# Generated by FakeRAM 2.0 (routing-friendly)
VERSION 5.7 ;
BUSBITCHARS "[]" ;
PROPERTYDEFINITIONS
  MACRO width INTEGER ;
  MACRO depth INTEGER ;
  MACRO banks INTEGER ;
END PROPERTYDEFINITIONS
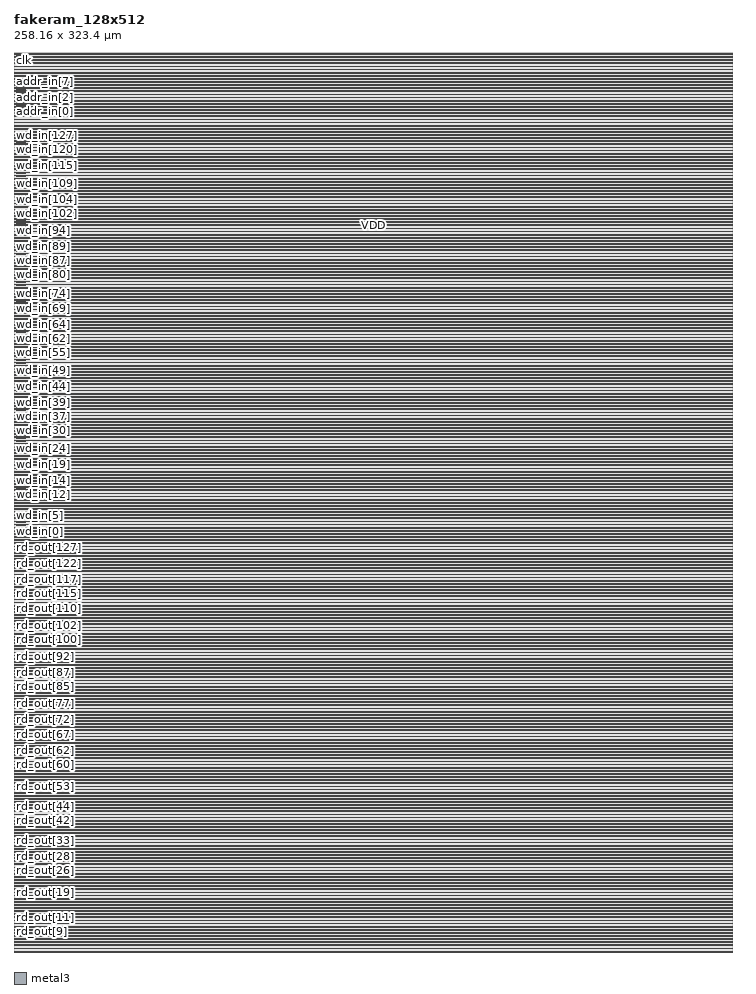
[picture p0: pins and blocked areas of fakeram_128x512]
MACRO fakeram_128x512
  PROPERTY width 128 ;
  PROPERTY depth 512 ;
  PROPERTY banks 4 ;
  FOREIGN fakeram_128x512 0 0 ;
  SYMMETRY X Y R90 ;
  SIZE 258.160 BY 323.400 ;
  CLASS BLOCK ;
  PIN rd_out[0]
    DIRECTION OUTPUT ;
    USE SIGNAL ;
    PORT
      LAYER metal3 ;
      RECT 1.000 0.140 3.000 0.210 ;
    END
    PORT
      LAYER metal3 ;
      RECT 1.000 0.105 4.000 0.245 ;
    END
  END rd_out[0]
  PIN rd_out[1]
    DIRECTION OUTPUT ;
    USE SIGNAL ;
    PORT
      LAYER metal3 ;
      RECT 1.000 1.260 3.000 1.330 ;
    END
    PORT
      LAYER metal3 ;
      RECT 1.000 1.225 4.000 1.365 ;
    END
  END rd_out[1]
  PIN rd_out[2]
    DIRECTION OUTPUT ;
    USE SIGNAL ;
    PORT
      LAYER metal3 ;
      RECT 1.000 2.380 3.000 2.450 ;
    END
    PORT
      LAYER metal3 ;
      RECT 1.000 2.345 4.000 2.485 ;
    END
  END rd_out[2]
  PIN rd_out[3]
    DIRECTION OUTPUT ;
    USE SIGNAL ;
    PORT
      LAYER metal3 ;
      RECT 1.000 3.500 3.000 3.570 ;
    END
    PORT
      LAYER metal3 ;
      RECT 1.000 3.465 4.000 3.605 ;
    END
  END rd_out[3]
  PIN rd_out[4]
    DIRECTION OUTPUT ;
    USE SIGNAL ;
    PORT
      LAYER metal3 ;
      RECT 1.000 4.620 3.000 4.690 ;
    END
    PORT
      LAYER metal3 ;
      RECT 1.000 4.585 4.000 4.725 ;
    END
  END rd_out[4]
  PIN rd_out[5]
    DIRECTION OUTPUT ;
    USE SIGNAL ;
    PORT
      LAYER metal3 ;
      RECT 1.000 5.740 3.000 5.810 ;
    END
    PORT
      LAYER metal3 ;
      RECT 1.000 5.705 4.000 5.845 ;
    END
  END rd_out[5]
  PIN rd_out[6]
    DIRECTION OUTPUT ;
    USE SIGNAL ;
    PORT
      LAYER metal3 ;
      RECT 1.000 6.860 3.000 6.930 ;
    END
    PORT
      LAYER metal3 ;
      RECT 1.000 6.825 4.000 6.965 ;
    END
  END rd_out[6]
  PIN rd_out[7]
    DIRECTION OUTPUT ;
    USE SIGNAL ;
    PORT
      LAYER metal3 ;
      RECT 1.000 7.980 3.000 8.050 ;
    END
    PORT
      LAYER metal3 ;
      RECT 1.000 7.945 4.000 8.085 ;
    END
  END rd_out[7]
  PIN rd_out[8]
    DIRECTION OUTPUT ;
    USE SIGNAL ;
    PORT
      LAYER metal3 ;
      RECT 1.000 9.100 3.000 9.170 ;
    END
    PORT
      LAYER metal3 ;
      RECT 1.000 9.065 4.000 9.205 ;
    END
  END rd_out[8]
  PIN rd_out[9]
    DIRECTION OUTPUT ;
    USE SIGNAL ;
    PORT
      LAYER metal3 ;
      RECT 1.000 10.220 3.000 10.290 ;
    END
    PORT
      LAYER metal3 ;
      RECT 1.000 10.185 4.000 10.325 ;
    END
  END rd_out[9]
  PIN rd_out[10]
    DIRECTION OUTPUT ;
    USE SIGNAL ;
    PORT
      LAYER metal3 ;
      RECT 1.000 11.340 3.000 11.410 ;
    END
    PORT
      LAYER metal3 ;
      RECT 1.000 11.305 4.000 11.445 ;
    END
  END rd_out[10]
  PIN rd_out[11]
    DIRECTION OUTPUT ;
    USE SIGNAL ;
    PORT
      LAYER metal3 ;
      RECT 1.000 12.460 3.000 12.530 ;
    END
    PORT
      LAYER metal3 ;
      RECT 1.000 12.425 4.000 12.565 ;
    END
  END rd_out[11]
  PIN rd_out[12]
    DIRECTION OUTPUT ;
    USE SIGNAL ;
    PORT
      LAYER metal3 ;
      RECT 1.000 13.580 3.000 13.650 ;
    END
    PORT
      LAYER metal3 ;
      RECT 1.000 13.545 4.000 13.685 ;
    END
  END rd_out[12]
  PIN rd_out[13]
    DIRECTION OUTPUT ;
    USE SIGNAL ;
    PORT
      LAYER metal3 ;
      RECT 1.000 14.700 3.000 14.770 ;
    END
    PORT
      LAYER metal3 ;
      RECT 1.000 14.665 4.000 14.805 ;
    END
  END rd_out[13]
  PIN rd_out[14]
    DIRECTION OUTPUT ;
    USE SIGNAL ;
    PORT
      LAYER metal3 ;
      RECT 1.000 15.820 3.000 15.890 ;
    END
    PORT
      LAYER metal3 ;
      RECT 1.000 15.785 4.000 15.925 ;
    END
  END rd_out[14]
  PIN rd_out[15]
    DIRECTION OUTPUT ;
    USE SIGNAL ;
    PORT
      LAYER metal3 ;
      RECT 1.000 16.940 3.000 17.010 ;
    END
    PORT
      LAYER metal3 ;
      RECT 1.000 16.905 4.000 17.045 ;
    END
  END rd_out[15]
  PIN rd_out[16]
    DIRECTION OUTPUT ;
    USE SIGNAL ;
    PORT
      LAYER metal3 ;
      RECT 1.000 18.060 3.000 18.130 ;
    END
    PORT
      LAYER metal3 ;
      RECT 1.000 18.025 4.000 18.165 ;
    END
  END rd_out[16]
  PIN rd_out[17]
    DIRECTION OUTPUT ;
    USE SIGNAL ;
    PORT
      LAYER metal3 ;
      RECT 1.000 19.180 3.000 19.250 ;
    END
    PORT
      LAYER metal3 ;
      RECT 1.000 19.145 4.000 19.285 ;
    END
  END rd_out[17]
  PIN rd_out[18]
    DIRECTION OUTPUT ;
    USE SIGNAL ;
    PORT
      LAYER metal3 ;
      RECT 1.000 20.300 3.000 20.370 ;
    END
    PORT
      LAYER metal3 ;
      RECT 1.000 20.265 4.000 20.405 ;
    END
  END rd_out[18]
  PIN rd_out[19]
    DIRECTION OUTPUT ;
    USE SIGNAL ;
    PORT
      LAYER metal3 ;
      RECT 1.000 21.420 3.000 21.490 ;
    END
    PORT
      LAYER metal3 ;
      RECT 1.000 21.385 4.000 21.525 ;
    END
  END rd_out[19]
  PIN rd_out[20]
    DIRECTION OUTPUT ;
    USE SIGNAL ;
    PORT
      LAYER metal3 ;
      RECT 1.000 22.540 3.000 22.610 ;
    END
    PORT
      LAYER metal3 ;
      RECT 1.000 22.505 4.000 22.645 ;
    END
  END rd_out[20]
  PIN rd_out[21]
    DIRECTION OUTPUT ;
    USE SIGNAL ;
    PORT
      LAYER metal3 ;
      RECT 1.000 23.660 3.000 23.730 ;
    END
    PORT
      LAYER metal3 ;
      RECT 1.000 23.625 4.000 23.765 ;
    END
  END rd_out[21]
  PIN rd_out[22]
    DIRECTION OUTPUT ;
    USE SIGNAL ;
    PORT
      LAYER metal3 ;
      RECT 1.000 24.780 3.000 24.850 ;
    END
    PORT
      LAYER metal3 ;
      RECT 1.000 24.745 4.000 24.885 ;
    END
  END rd_out[22]
  PIN rd_out[23]
    DIRECTION OUTPUT ;
    USE SIGNAL ;
    PORT
      LAYER metal3 ;
      RECT 1.000 25.900 3.000 25.970 ;
    END
    PORT
      LAYER metal3 ;
      RECT 1.000 25.865 4.000 26.005 ;
    END
  END rd_out[23]
  PIN rd_out[24]
    DIRECTION OUTPUT ;
    USE SIGNAL ;
    PORT
      LAYER metal3 ;
      RECT 1.000 27.020 3.000 27.090 ;
    END
    PORT
      LAYER metal3 ;
      RECT 1.000 26.985 4.000 27.125 ;
    END
  END rd_out[24]
  PIN rd_out[25]
    DIRECTION OUTPUT ;
    USE SIGNAL ;
    PORT
      LAYER metal3 ;
      RECT 1.000 28.140 3.000 28.210 ;
    END
    PORT
      LAYER metal3 ;
      RECT 1.000 28.105 4.000 28.245 ;
    END
  END rd_out[25]
  PIN rd_out[26]
    DIRECTION OUTPUT ;
    USE SIGNAL ;
    PORT
      LAYER metal3 ;
      RECT 1.000 29.260 3.000 29.330 ;
    END
    PORT
      LAYER metal3 ;
      RECT 1.000 29.225 4.000 29.365 ;
    END
  END rd_out[26]
  PIN rd_out[27]
    DIRECTION OUTPUT ;
    USE SIGNAL ;
    PORT
      LAYER metal3 ;
      RECT 1.000 30.380 3.000 30.450 ;
    END
    PORT
      LAYER metal3 ;
      RECT 1.000 30.345 4.000 30.485 ;
    END
  END rd_out[27]
  PIN rd_out[28]
    DIRECTION OUTPUT ;
    USE SIGNAL ;
    PORT
      LAYER metal3 ;
      RECT 1.000 31.500 3.000 31.570 ;
    END
    PORT
      LAYER metal3 ;
      RECT 1.000 31.465 4.000 31.605 ;
    END
  END rd_out[28]
  PIN rd_out[29]
    DIRECTION OUTPUT ;
    USE SIGNAL ;
    PORT
      LAYER metal3 ;
      RECT 1.000 32.620 3.000 32.690 ;
    END
    PORT
      LAYER metal3 ;
      RECT 1.000 32.585 4.000 32.725 ;
    END
  END rd_out[29]
  PIN rd_out[30]
    DIRECTION OUTPUT ;
    USE SIGNAL ;
    PORT
      LAYER metal3 ;
      RECT 1.000 33.740 3.000 33.810 ;
    END
    PORT
      LAYER metal3 ;
      RECT 1.000 33.705 4.000 33.845 ;
    END
  END rd_out[30]
  PIN rd_out[31]
    DIRECTION OUTPUT ;
    USE SIGNAL ;
    PORT
      LAYER metal3 ;
      RECT 1.000 34.860 3.000 34.930 ;
    END
    PORT
      LAYER metal3 ;
      RECT 1.000 34.825 4.000 34.965 ;
    END
  END rd_out[31]
  PIN rd_out[32]
    DIRECTION OUTPUT ;
    USE SIGNAL ;
    PORT
      LAYER metal3 ;
      RECT 1.000 35.980 3.000 36.050 ;
    END
    PORT
      LAYER metal3 ;
      RECT 1.000 35.945 4.000 36.085 ;
    END
  END rd_out[32]
  PIN rd_out[33]
    DIRECTION OUTPUT ;
    USE SIGNAL ;
    PORT
      LAYER metal3 ;
      RECT 1.000 37.100 3.000 37.170 ;
    END
    PORT
      LAYER metal3 ;
      RECT 1.000 37.065 4.000 37.205 ;
    END
  END rd_out[33]
  PIN rd_out[34]
    DIRECTION OUTPUT ;
    USE SIGNAL ;
    PORT
      LAYER metal3 ;
      RECT 1.000 38.220 3.000 38.290 ;
    END
    PORT
      LAYER metal3 ;
      RECT 1.000 38.185 4.000 38.325 ;
    END
  END rd_out[34]
  PIN rd_out[35]
    DIRECTION OUTPUT ;
    USE SIGNAL ;
    PORT
      LAYER metal3 ;
      RECT 1.000 39.340 3.000 39.410 ;
    END
    PORT
      LAYER metal3 ;
      RECT 1.000 39.305 4.000 39.445 ;
    END
  END rd_out[35]
  PIN rd_out[36]
    DIRECTION OUTPUT ;
    USE SIGNAL ;
    PORT
      LAYER metal3 ;
      RECT 1.000 40.460 3.000 40.530 ;
    END
    PORT
      LAYER metal3 ;
      RECT 1.000 40.425 4.000 40.565 ;
    END
  END rd_out[36]
  PIN rd_out[37]
    DIRECTION OUTPUT ;
    USE SIGNAL ;
    PORT
      LAYER metal3 ;
      RECT 1.000 41.580 3.000 41.650 ;
    END
    PORT
      LAYER metal3 ;
      RECT 1.000 41.545 4.000 41.685 ;
    END
  END rd_out[37]
  PIN rd_out[38]
    DIRECTION OUTPUT ;
    USE SIGNAL ;
    PORT
      LAYER metal3 ;
      RECT 1.000 42.700 3.000 42.770 ;
    END
    PORT
      LAYER metal3 ;
      RECT 1.000 42.665 4.000 42.805 ;
    END
  END rd_out[38]
  PIN rd_out[39]
    DIRECTION OUTPUT ;
    USE SIGNAL ;
    PORT
      LAYER metal3 ;
      RECT 1.000 43.820 3.000 43.890 ;
    END
    PORT
      LAYER metal3 ;
      RECT 1.000 43.785 4.000 43.925 ;
    END
  END rd_out[39]
  PIN rd_out[40]
    DIRECTION OUTPUT ;
    USE SIGNAL ;
    PORT
      LAYER metal3 ;
      RECT 1.000 44.940 3.000 45.010 ;
    END
    PORT
      LAYER metal3 ;
      RECT 1.000 44.905 4.000 45.045 ;
    END
  END rd_out[40]
  PIN rd_out[41]
    DIRECTION OUTPUT ;
    USE SIGNAL ;
    PORT
      LAYER metal3 ;
      RECT 1.000 46.060 3.000 46.130 ;
    END
    PORT
      LAYER metal3 ;
      RECT 1.000 46.025 4.000 46.165 ;
    END
  END rd_out[41]
  PIN rd_out[42]
    DIRECTION OUTPUT ;
    USE SIGNAL ;
    PORT
      LAYER metal3 ;
      RECT 1.000 47.180 3.000 47.250 ;
    END
    PORT
      LAYER metal3 ;
      RECT 1.000 47.145 4.000 47.285 ;
    END
  END rd_out[42]
  PIN rd_out[43]
    DIRECTION OUTPUT ;
    USE SIGNAL ;
    PORT
      LAYER metal3 ;
      RECT 1.000 48.300 3.000 48.370 ;
    END
    PORT
      LAYER metal3 ;
      RECT 1.000 48.265 4.000 48.405 ;
    END
  END rd_out[43]
  PIN rd_out[44]
    DIRECTION OUTPUT ;
    USE SIGNAL ;
    PORT
      LAYER metal3 ;
      RECT 1.000 49.420 3.000 49.490 ;
    END
    PORT
      LAYER metal3 ;
      RECT 1.000 49.385 4.000 49.525 ;
    END
  END rd_out[44]
  PIN rd_out[45]
    DIRECTION OUTPUT ;
    USE SIGNAL ;
    PORT
      LAYER metal3 ;
      RECT 1.000 50.540 3.000 50.610 ;
    END
    PORT
      LAYER metal3 ;
      RECT 1.000 50.505 4.000 50.645 ;
    END
  END rd_out[45]
  PIN rd_out[46]
    DIRECTION OUTPUT ;
    USE SIGNAL ;
    PORT
      LAYER metal3 ;
      RECT 1.000 51.660 3.000 51.730 ;
    END
    PORT
      LAYER metal3 ;
      RECT 1.000 51.625 4.000 51.765 ;
    END
  END rd_out[46]
  PIN rd_out[47]
    DIRECTION OUTPUT ;
    USE SIGNAL ;
    PORT
      LAYER metal3 ;
      RECT 1.000 52.780 3.000 52.850 ;
    END
    PORT
      LAYER metal3 ;
      RECT 1.000 52.745 4.000 52.885 ;
    END
  END rd_out[47]
  PIN rd_out[48]
    DIRECTION OUTPUT ;
    USE SIGNAL ;
    PORT
      LAYER metal3 ;
      RECT 1.000 53.900 3.000 53.970 ;
    END
    PORT
      LAYER metal3 ;
      RECT 1.000 53.865 4.000 54.005 ;
    END
  END rd_out[48]
  PIN rd_out[49]
    DIRECTION OUTPUT ;
    USE SIGNAL ;
    PORT
      LAYER metal3 ;
      RECT 1.000 55.020 3.000 55.090 ;
    END
    PORT
      LAYER metal3 ;
      RECT 1.000 54.985 4.000 55.125 ;
    END
  END rd_out[49]
  PIN rd_out[50]
    DIRECTION OUTPUT ;
    USE SIGNAL ;
    PORT
      LAYER metal3 ;
      RECT 1.000 56.140 3.000 56.210 ;
    END
    PORT
      LAYER metal3 ;
      RECT 1.000 56.105 4.000 56.245 ;
    END
  END rd_out[50]
  PIN rd_out[51]
    DIRECTION OUTPUT ;
    USE SIGNAL ;
    PORT
      LAYER metal3 ;
      RECT 1.000 57.260 3.000 57.330 ;
    END
    PORT
      LAYER metal3 ;
      RECT 1.000 57.225 4.000 57.365 ;
    END
  END rd_out[51]
  PIN rd_out[52]
    DIRECTION OUTPUT ;
    USE SIGNAL ;
    PORT
      LAYER metal3 ;
      RECT 1.000 58.380 3.000 58.450 ;
    END
    PORT
      LAYER metal3 ;
      RECT 1.000 58.345 4.000 58.485 ;
    END
  END rd_out[52]
  PIN rd_out[53]
    DIRECTION OUTPUT ;
    USE SIGNAL ;
    PORT
      LAYER metal3 ;
      RECT 1.000 59.500 3.000 59.570 ;
    END
    PORT
      LAYER metal3 ;
      RECT 1.000 59.465 4.000 59.605 ;
    END
  END rd_out[53]
  PIN rd_out[54]
    DIRECTION OUTPUT ;
    USE SIGNAL ;
    PORT
      LAYER metal3 ;
      RECT 1.000 60.620 3.000 60.690 ;
    END
    PORT
      LAYER metal3 ;
      RECT 1.000 60.585 4.000 60.725 ;
    END
  END rd_out[54]
  PIN rd_out[55]
    DIRECTION OUTPUT ;
    USE SIGNAL ;
    PORT
      LAYER metal3 ;
      RECT 1.000 61.740 3.000 61.810 ;
    END
    PORT
      LAYER metal3 ;
      RECT 1.000 61.705 4.000 61.845 ;
    END
  END rd_out[55]
  PIN rd_out[56]
    DIRECTION OUTPUT ;
    USE SIGNAL ;
    PORT
      LAYER metal3 ;
      RECT 1.000 62.860 3.000 62.930 ;
    END
    PORT
      LAYER metal3 ;
      RECT 1.000 62.825 4.000 62.965 ;
    END
  END rd_out[56]
  PIN rd_out[57]
    DIRECTION OUTPUT ;
    USE SIGNAL ;
    PORT
      LAYER metal3 ;
      RECT 1.000 63.980 3.000 64.050 ;
    END
    PORT
      LAYER metal3 ;
      RECT 1.000 63.945 4.000 64.085 ;
    END
  END rd_out[57]
  PIN rd_out[58]
    DIRECTION OUTPUT ;
    USE SIGNAL ;
    PORT
      LAYER metal3 ;
      RECT 1.000 65.100 3.000 65.170 ;
    END
    PORT
      LAYER metal3 ;
      RECT 1.000 65.065 4.000 65.205 ;
    END
  END rd_out[58]
  PIN rd_out[59]
    DIRECTION OUTPUT ;
    USE SIGNAL ;
    PORT
      LAYER metal3 ;
      RECT 1.000 66.220 3.000 66.290 ;
    END
    PORT
      LAYER metal3 ;
      RECT 1.000 66.185 4.000 66.325 ;
    END
  END rd_out[59]
  PIN rd_out[60]
    DIRECTION OUTPUT ;
    USE SIGNAL ;
    PORT
      LAYER metal3 ;
      RECT 1.000 67.340 3.000 67.410 ;
    END
    PORT
      LAYER metal3 ;
      RECT 1.000 67.305 4.000 67.445 ;
    END
  END rd_out[60]
  PIN rd_out[61]
    DIRECTION OUTPUT ;
    USE SIGNAL ;
    PORT
      LAYER metal3 ;
      RECT 1.000 68.460 3.000 68.530 ;
    END
    PORT
      LAYER metal3 ;
      RECT 1.000 68.425 4.000 68.565 ;
    END
  END rd_out[61]
  PIN rd_out[62]
    DIRECTION OUTPUT ;
    USE SIGNAL ;
    PORT
      LAYER metal3 ;
      RECT 1.000 69.580 3.000 69.650 ;
    END
    PORT
      LAYER metal3 ;
      RECT 1.000 69.545 4.000 69.685 ;
    END
  END rd_out[62]
  PIN rd_out[63]
    DIRECTION OUTPUT ;
    USE SIGNAL ;
    PORT
      LAYER metal3 ;
      RECT 1.000 70.700 3.000 70.770 ;
    END
    PORT
      LAYER metal3 ;
      RECT 1.000 70.665 4.000 70.805 ;
    END
  END rd_out[63]
  PIN rd_out[64]
    DIRECTION OUTPUT ;
    USE SIGNAL ;
    PORT
      LAYER metal3 ;
      RECT 1.000 71.820 3.000 71.890 ;
    END
    PORT
      LAYER metal3 ;
      RECT 1.000 71.785 4.000 71.925 ;
    END
  END rd_out[64]
  PIN rd_out[65]
    DIRECTION OUTPUT ;
    USE SIGNAL ;
    PORT
      LAYER metal3 ;
      RECT 1.000 72.940 3.000 73.010 ;
    END
    PORT
      LAYER metal3 ;
      RECT 1.000 72.905 4.000 73.045 ;
    END
  END rd_out[65]
  PIN rd_out[66]
    DIRECTION OUTPUT ;
    USE SIGNAL ;
    PORT
      LAYER metal3 ;
      RECT 1.000 74.060 3.000 74.130 ;
    END
    PORT
      LAYER metal3 ;
      RECT 1.000 74.025 4.000 74.165 ;
    END
  END rd_out[66]
  PIN rd_out[67]
    DIRECTION OUTPUT ;
    USE SIGNAL ;
    PORT
      LAYER metal3 ;
      RECT 1.000 75.180 3.000 75.250 ;
    END
    PORT
      LAYER metal3 ;
      RECT 1.000 75.145 4.000 75.285 ;
    END
  END rd_out[67]
  PIN rd_out[68]
    DIRECTION OUTPUT ;
    USE SIGNAL ;
    PORT
      LAYER metal3 ;
      RECT 1.000 76.300 3.000 76.370 ;
    END
    PORT
      LAYER metal3 ;
      RECT 1.000 76.265 4.000 76.405 ;
    END
  END rd_out[68]
  PIN rd_out[69]
    DIRECTION OUTPUT ;
    USE SIGNAL ;
    PORT
      LAYER metal3 ;
      RECT 1.000 77.420 3.000 77.490 ;
    END
    PORT
      LAYER metal3 ;
      RECT 1.000 77.385 4.000 77.525 ;
    END
  END rd_out[69]
  PIN rd_out[70]
    DIRECTION OUTPUT ;
    USE SIGNAL ;
    PORT
      LAYER metal3 ;
      RECT 1.000 78.540 3.000 78.610 ;
    END
    PORT
      LAYER metal3 ;
      RECT 1.000 78.505 4.000 78.645 ;
    END
  END rd_out[70]
  PIN rd_out[71]
    DIRECTION OUTPUT ;
    USE SIGNAL ;
    PORT
      LAYER metal3 ;
      RECT 1.000 79.660 3.000 79.730 ;
    END
    PORT
      LAYER metal3 ;
      RECT 1.000 79.625 4.000 79.765 ;
    END
  END rd_out[71]
  PIN rd_out[72]
    DIRECTION OUTPUT ;
    USE SIGNAL ;
    PORT
      LAYER metal3 ;
      RECT 1.000 80.780 3.000 80.850 ;
    END
    PORT
      LAYER metal3 ;
      RECT 1.000 80.745 4.000 80.885 ;
    END
  END rd_out[72]
  PIN rd_out[73]
    DIRECTION OUTPUT ;
    USE SIGNAL ;
    PORT
      LAYER metal3 ;
      RECT 1.000 81.900 3.000 81.970 ;
    END
    PORT
      LAYER metal3 ;
      RECT 1.000 81.865 4.000 82.005 ;
    END
  END rd_out[73]
  PIN rd_out[74]
    DIRECTION OUTPUT ;
    USE SIGNAL ;
    PORT
      LAYER metal3 ;
      RECT 1.000 83.020 3.000 83.090 ;
    END
    PORT
      LAYER metal3 ;
      RECT 1.000 82.985 4.000 83.125 ;
    END
  END rd_out[74]
  PIN rd_out[75]
    DIRECTION OUTPUT ;
    USE SIGNAL ;
    PORT
      LAYER metal3 ;
      RECT 1.000 84.140 3.000 84.210 ;
    END
    PORT
      LAYER metal3 ;
      RECT 1.000 84.105 4.000 84.245 ;
    END
  END rd_out[75]
  PIN rd_out[76]
    DIRECTION OUTPUT ;
    USE SIGNAL ;
    PORT
      LAYER metal3 ;
      RECT 1.000 85.260 3.000 85.330 ;
    END
    PORT
      LAYER metal3 ;
      RECT 1.000 85.225 4.000 85.365 ;
    END
  END rd_out[76]
  PIN rd_out[77]
    DIRECTION OUTPUT ;
    USE SIGNAL ;
    PORT
      LAYER metal3 ;
      RECT 1.000 86.380 3.000 86.450 ;
    END
    PORT
      LAYER metal3 ;
      RECT 1.000 86.345 4.000 86.485 ;
    END
  END rd_out[77]
  PIN rd_out[78]
    DIRECTION OUTPUT ;
    USE SIGNAL ;
    PORT
      LAYER metal3 ;
      RECT 1.000 87.500 3.000 87.570 ;
    END
    PORT
      LAYER metal3 ;
      RECT 1.000 87.465 4.000 87.605 ;
    END
  END rd_out[78]
  PIN rd_out[79]
    DIRECTION OUTPUT ;
    USE SIGNAL ;
    PORT
      LAYER metal3 ;
      RECT 1.000 88.620 3.000 88.690 ;
    END
    PORT
      LAYER metal3 ;
      RECT 1.000 88.585 4.000 88.725 ;
    END
  END rd_out[79]
  PIN rd_out[80]
    DIRECTION OUTPUT ;
    USE SIGNAL ;
    PORT
      LAYER metal3 ;
      RECT 1.000 89.740 3.000 89.810 ;
    END
    PORT
      LAYER metal3 ;
      RECT 1.000 89.705 4.000 89.845 ;
    END
  END rd_out[80]
  PIN rd_out[81]
    DIRECTION OUTPUT ;
    USE SIGNAL ;
    PORT
      LAYER metal3 ;
      RECT 1.000 90.860 3.000 90.930 ;
    END
    PORT
      LAYER metal3 ;
      RECT 1.000 90.825 4.000 90.965 ;
    END
  END rd_out[81]
  PIN rd_out[82]
    DIRECTION OUTPUT ;
    USE SIGNAL ;
    PORT
      LAYER metal3 ;
      RECT 1.000 91.980 3.000 92.050 ;
    END
    PORT
      LAYER metal3 ;
      RECT 1.000 91.945 4.000 92.085 ;
    END
  END rd_out[82]
  PIN rd_out[83]
    DIRECTION OUTPUT ;
    USE SIGNAL ;
    PORT
      LAYER metal3 ;
      RECT 1.000 93.100 3.000 93.170 ;
    END
    PORT
      LAYER metal3 ;
      RECT 1.000 93.065 4.000 93.205 ;
    END
  END rd_out[83]
  PIN rd_out[84]
    DIRECTION OUTPUT ;
    USE SIGNAL ;
    PORT
      LAYER metal3 ;
      RECT 1.000 94.220 3.000 94.290 ;
    END
    PORT
      LAYER metal3 ;
      RECT 1.000 94.185 4.000 94.325 ;
    END
  END rd_out[84]
  PIN rd_out[85]
    DIRECTION OUTPUT ;
    USE SIGNAL ;
    PORT
      LAYER metal3 ;
      RECT 1.000 95.340 3.000 95.410 ;
    END
    PORT
      LAYER metal3 ;
      RECT 1.000 95.305 4.000 95.445 ;
    END
  END rd_out[85]
  PIN rd_out[86]
    DIRECTION OUTPUT ;
    USE SIGNAL ;
    PORT
      LAYER metal3 ;
      RECT 1.000 96.460 3.000 96.530 ;
    END
    PORT
      LAYER metal3 ;
      RECT 1.000 96.425 4.000 96.565 ;
    END
  END rd_out[86]
  PIN rd_out[87]
    DIRECTION OUTPUT ;
    USE SIGNAL ;
    PORT
      LAYER metal3 ;
      RECT 1.000 97.580 3.000 97.650 ;
    END
    PORT
      LAYER metal3 ;
      RECT 1.000 97.545 4.000 97.685 ;
    END
  END rd_out[87]
  PIN rd_out[88]
    DIRECTION OUTPUT ;
    USE SIGNAL ;
    PORT
      LAYER metal3 ;
      RECT 1.000 98.700 3.000 98.770 ;
    END
    PORT
      LAYER metal3 ;
      RECT 1.000 98.665 4.000 98.805 ;
    END
  END rd_out[88]
  PIN rd_out[89]
    DIRECTION OUTPUT ;
    USE SIGNAL ;
    PORT
      LAYER metal3 ;
      RECT 1.000 99.820 3.000 99.890 ;
    END
    PORT
      LAYER metal3 ;
      RECT 1.000 99.785 4.000 99.925 ;
    END
  END rd_out[89]
  PIN rd_out[90]
    DIRECTION OUTPUT ;
    USE SIGNAL ;
    PORT
      LAYER metal3 ;
      RECT 1.000 100.940 3.000 101.010 ;
    END
    PORT
      LAYER metal3 ;
      RECT 1.000 100.905 4.000 101.045 ;
    END
  END rd_out[90]
  PIN rd_out[91]
    DIRECTION OUTPUT ;
    USE SIGNAL ;
    PORT
      LAYER metal3 ;
      RECT 1.000 102.060 3.000 102.130 ;
    END
    PORT
      LAYER metal3 ;
      RECT 1.000 102.025 4.000 102.165 ;
    END
  END rd_out[91]
  PIN rd_out[92]
    DIRECTION OUTPUT ;
    USE SIGNAL ;
    PORT
      LAYER metal3 ;
      RECT 1.000 103.180 3.000 103.250 ;
    END
    PORT
      LAYER metal3 ;
      RECT 1.000 103.145 4.000 103.285 ;
    END
  END rd_out[92]
  PIN rd_out[93]
    DIRECTION OUTPUT ;
    USE SIGNAL ;
    PORT
      LAYER metal3 ;
      RECT 1.000 104.300 3.000 104.370 ;
    END
    PORT
      LAYER metal3 ;
      RECT 1.000 104.265 4.000 104.405 ;
    END
  END rd_out[93]
  PIN rd_out[94]
    DIRECTION OUTPUT ;
    USE SIGNAL ;
    PORT
      LAYER metal3 ;
      RECT 1.000 105.420 3.000 105.490 ;
    END
    PORT
      LAYER metal3 ;
      RECT 1.000 105.385 4.000 105.525 ;
    END
  END rd_out[94]
  PIN rd_out[95]
    DIRECTION OUTPUT ;
    USE SIGNAL ;
    PORT
      LAYER metal3 ;
      RECT 1.000 106.540 3.000 106.610 ;
    END
    PORT
      LAYER metal3 ;
      RECT 1.000 106.505 4.000 106.645 ;
    END
  END rd_out[95]
  PIN rd_out[96]
    DIRECTION OUTPUT ;
    USE SIGNAL ;
    PORT
      LAYER metal3 ;
      RECT 1.000 107.660 3.000 107.730 ;
    END
    PORT
      LAYER metal3 ;
      RECT 1.000 107.625 4.000 107.765 ;
    END
  END rd_out[96]
  PIN rd_out[97]
    DIRECTION OUTPUT ;
    USE SIGNAL ;
    PORT
      LAYER metal3 ;
      RECT 1.000 108.780 3.000 108.850 ;
    END
    PORT
      LAYER metal3 ;
      RECT 1.000 108.745 4.000 108.885 ;
    END
  END rd_out[97]
  PIN rd_out[98]
    DIRECTION OUTPUT ;
    USE SIGNAL ;
    PORT
      LAYER metal3 ;
      RECT 1.000 109.900 3.000 109.970 ;
    END
    PORT
      LAYER metal3 ;
      RECT 1.000 109.865 4.000 110.005 ;
    END
  END rd_out[98]
  PIN rd_out[99]
    DIRECTION OUTPUT ;
    USE SIGNAL ;
    PORT
      LAYER metal3 ;
      RECT 1.000 111.020 3.000 111.090 ;
    END
    PORT
      LAYER metal3 ;
      RECT 1.000 110.985 4.000 111.125 ;
    END
  END rd_out[99]
  PIN rd_out[100]
    DIRECTION OUTPUT ;
    USE SIGNAL ;
    PORT
      LAYER metal3 ;
      RECT 1.000 112.140 3.000 112.210 ;
    END
    PORT
      LAYER metal3 ;
      RECT 1.000 112.105 4.000 112.245 ;
    END
  END rd_out[100]
  PIN rd_out[101]
    DIRECTION OUTPUT ;
    USE SIGNAL ;
    PORT
      LAYER metal3 ;
      RECT 1.000 113.260 3.000 113.330 ;
    END
    PORT
      LAYER metal3 ;
      RECT 1.000 113.225 4.000 113.365 ;
    END
  END rd_out[101]
  PIN rd_out[102]
    DIRECTION OUTPUT ;
    USE SIGNAL ;
    PORT
      LAYER metal3 ;
      RECT 1.000 114.380 3.000 114.450 ;
    END
    PORT
      LAYER metal3 ;
      RECT 1.000 114.345 4.000 114.485 ;
    END
  END rd_out[102]
  PIN rd_out[103]
    DIRECTION OUTPUT ;
    USE SIGNAL ;
    PORT
      LAYER metal3 ;
      RECT 1.000 115.500 3.000 115.570 ;
    END
    PORT
      LAYER metal3 ;
      RECT 1.000 115.465 4.000 115.605 ;
    END
  END rd_out[103]
  PIN rd_out[104]
    DIRECTION OUTPUT ;
    USE SIGNAL ;
    PORT
      LAYER metal3 ;
      RECT 1.000 116.620 3.000 116.690 ;
    END
    PORT
      LAYER metal3 ;
      RECT 1.000 116.585 4.000 116.725 ;
    END
  END rd_out[104]
  PIN rd_out[105]
    DIRECTION OUTPUT ;
    USE SIGNAL ;
    PORT
      LAYER metal3 ;
      RECT 1.000 117.740 3.000 117.810 ;
    END
    PORT
      LAYER metal3 ;
      RECT 1.000 117.705 4.000 117.845 ;
    END
  END rd_out[105]
  PIN rd_out[106]
    DIRECTION OUTPUT ;
    USE SIGNAL ;
    PORT
      LAYER metal3 ;
      RECT 1.000 118.860 3.000 118.930 ;
    END
    PORT
      LAYER metal3 ;
      RECT 1.000 118.825 4.000 118.965 ;
    END
  END rd_out[106]
  PIN rd_out[107]
    DIRECTION OUTPUT ;
    USE SIGNAL ;
    PORT
      LAYER metal3 ;
      RECT 1.000 119.980 3.000 120.050 ;
    END
    PORT
      LAYER metal3 ;
      RECT 1.000 119.945 4.000 120.085 ;
    END
  END rd_out[107]
  PIN rd_out[108]
    DIRECTION OUTPUT ;
    USE SIGNAL ;
    PORT
      LAYER metal3 ;
      RECT 1.000 121.100 3.000 121.170 ;
    END
    PORT
      LAYER metal3 ;
      RECT 1.000 121.065 4.000 121.205 ;
    END
  END rd_out[108]
  PIN rd_out[109]
    DIRECTION OUTPUT ;
    USE SIGNAL ;
    PORT
      LAYER metal3 ;
      RECT 1.000 122.220 3.000 122.290 ;
    END
    PORT
      LAYER metal3 ;
      RECT 1.000 122.185 4.000 122.325 ;
    END
  END rd_out[109]
  PIN rd_out[110]
    DIRECTION OUTPUT ;
    USE SIGNAL ;
    PORT
      LAYER metal3 ;
      RECT 1.000 123.340 3.000 123.410 ;
    END
    PORT
      LAYER metal3 ;
      RECT 1.000 123.305 4.000 123.445 ;
    END
  END rd_out[110]
  PIN rd_out[111]
    DIRECTION OUTPUT ;
    USE SIGNAL ;
    PORT
      LAYER metal3 ;
      RECT 1.000 124.460 3.000 124.530 ;
    END
    PORT
      LAYER metal3 ;
      RECT 1.000 124.425 4.000 124.565 ;
    END
  END rd_out[111]
  PIN rd_out[112]
    DIRECTION OUTPUT ;
    USE SIGNAL ;
    PORT
      LAYER metal3 ;
      RECT 1.000 125.580 3.000 125.650 ;
    END
    PORT
      LAYER metal3 ;
      RECT 1.000 125.545 4.000 125.685 ;
    END
  END rd_out[112]
  PIN rd_out[113]
    DIRECTION OUTPUT ;
    USE SIGNAL ;
    PORT
      LAYER metal3 ;
      RECT 1.000 126.700 3.000 126.770 ;
    END
    PORT
      LAYER metal3 ;
      RECT 1.000 126.665 4.000 126.805 ;
    END
  END rd_out[113]
  PIN rd_out[114]
    DIRECTION OUTPUT ;
    USE SIGNAL ;
    PORT
      LAYER metal3 ;
      RECT 1.000 127.820 3.000 127.890 ;
    END
    PORT
      LAYER metal3 ;
      RECT 1.000 127.785 4.000 127.925 ;
    END
  END rd_out[114]
  PIN rd_out[115]
    DIRECTION OUTPUT ;
    USE SIGNAL ;
    PORT
      LAYER metal3 ;
      RECT 1.000 128.940 3.000 129.010 ;
    END
    PORT
      LAYER metal3 ;
      RECT 1.000 128.905 4.000 129.045 ;
    END
  END rd_out[115]
  PIN rd_out[116]
    DIRECTION OUTPUT ;
    USE SIGNAL ;
    PORT
      LAYER metal3 ;
      RECT 1.000 130.060 3.000 130.130 ;
    END
    PORT
      LAYER metal3 ;
      RECT 1.000 130.025 4.000 130.165 ;
    END
  END rd_out[116]
  PIN rd_out[117]
    DIRECTION OUTPUT ;
    USE SIGNAL ;
    PORT
      LAYER metal3 ;
      RECT 1.000 131.180 3.000 131.250 ;
    END
    PORT
      LAYER metal3 ;
      RECT 1.000 131.145 4.000 131.285 ;
    END
  END rd_out[117]
  PIN rd_out[118]
    DIRECTION OUTPUT ;
    USE SIGNAL ;
    PORT
      LAYER metal3 ;
      RECT 1.000 132.300 3.000 132.370 ;
    END
    PORT
      LAYER metal3 ;
      RECT 1.000 132.265 4.000 132.405 ;
    END
  END rd_out[118]
  PIN rd_out[119]
    DIRECTION OUTPUT ;
    USE SIGNAL ;
    PORT
      LAYER metal3 ;
      RECT 1.000 133.420 3.000 133.490 ;
    END
    PORT
      LAYER metal3 ;
      RECT 1.000 133.385 4.000 133.525 ;
    END
  END rd_out[119]
  PIN rd_out[120]
    DIRECTION OUTPUT ;
    USE SIGNAL ;
    PORT
      LAYER metal3 ;
      RECT 1.000 134.540 3.000 134.610 ;
    END
    PORT
      LAYER metal3 ;
      RECT 1.000 134.505 4.000 134.645 ;
    END
  END rd_out[120]
  PIN rd_out[121]
    DIRECTION OUTPUT ;
    USE SIGNAL ;
    PORT
      LAYER metal3 ;
      RECT 1.000 135.660 3.000 135.730 ;
    END
    PORT
      LAYER metal3 ;
      RECT 1.000 135.625 4.000 135.765 ;
    END
  END rd_out[121]
  PIN rd_out[122]
    DIRECTION OUTPUT ;
    USE SIGNAL ;
    PORT
      LAYER metal3 ;
      RECT 1.000 136.780 3.000 136.850 ;
    END
    PORT
      LAYER metal3 ;
      RECT 1.000 136.745 4.000 136.885 ;
    END
  END rd_out[122]
  PIN rd_out[123]
    DIRECTION OUTPUT ;
    USE SIGNAL ;
    PORT
      LAYER metal3 ;
      RECT 1.000 137.900 3.000 137.970 ;
    END
    PORT
      LAYER metal3 ;
      RECT 1.000 137.865 4.000 138.005 ;
    END
  END rd_out[123]
  PIN rd_out[124]
    DIRECTION OUTPUT ;
    USE SIGNAL ;
    PORT
      LAYER metal3 ;
      RECT 1.000 139.020 3.000 139.090 ;
    END
    PORT
      LAYER metal3 ;
      RECT 1.000 138.985 4.000 139.125 ;
    END
  END rd_out[124]
  PIN rd_out[125]
    DIRECTION OUTPUT ;
    USE SIGNAL ;
    PORT
      LAYER metal3 ;
      RECT 1.000 140.140 3.000 140.210 ;
    END
    PORT
      LAYER metal3 ;
      RECT 1.000 140.105 4.000 140.245 ;
    END
  END rd_out[125]
  PIN rd_out[126]
    DIRECTION OUTPUT ;
    USE SIGNAL ;
    PORT
      LAYER metal3 ;
      RECT 1.000 141.260 3.000 141.330 ;
    END
    PORT
      LAYER metal3 ;
      RECT 1.000 141.225 4.000 141.365 ;
    END
  END rd_out[126]
  PIN rd_out[127]
    DIRECTION OUTPUT ;
    USE SIGNAL ;
    PORT
      LAYER metal3 ;
      RECT 1.000 142.380 3.000 142.450 ;
    END
    PORT
      LAYER metal3 ;
      RECT 1.000 142.345 4.000 142.485 ;
    END
  END rd_out[127]
  PIN wd_in[0]
    DIRECTION INPUT ;
    USE SIGNAL ;
    PORT
      LAYER metal3 ;
      RECT 1.000 151.060 3.000 151.130 ;
    END
    PORT
      LAYER metal3 ;
      RECT 1.000 151.025 4.000 151.165 ;
    END
  END wd_in[0]
  PIN wd_in[1]
    DIRECTION INPUT ;
    USE SIGNAL ;
    PORT
      LAYER metal3 ;
      RECT 1.000 152.180 3.000 152.250 ;
    END
    PORT
      LAYER metal3 ;
      RECT 1.000 152.145 4.000 152.285 ;
    END
  END wd_in[1]
  PIN wd_in[2]
    DIRECTION INPUT ;
    USE SIGNAL ;
    PORT
      LAYER metal3 ;
      RECT 1.000 153.300 3.000 153.370 ;
    END
    PORT
      LAYER metal3 ;
      RECT 1.000 153.265 4.000 153.405 ;
    END
  END wd_in[2]
  PIN wd_in[3]
    DIRECTION INPUT ;
    USE SIGNAL ;
    PORT
      LAYER metal3 ;
      RECT 1.000 154.420 3.000 154.490 ;
    END
    PORT
      LAYER metal3 ;
      RECT 1.000 154.385 4.000 154.525 ;
    END
  END wd_in[3]
  PIN wd_in[4]
    DIRECTION INPUT ;
    USE SIGNAL ;
    PORT
      LAYER metal3 ;
      RECT 1.000 155.540 3.000 155.610 ;
    END
    PORT
      LAYER metal3 ;
      RECT 1.000 155.505 4.000 155.645 ;
    END
  END wd_in[4]
  PIN wd_in[5]
    DIRECTION INPUT ;
    USE SIGNAL ;
    PORT
      LAYER metal3 ;
      RECT 1.000 156.660 3.000 156.730 ;
    END
    PORT
      LAYER metal3 ;
      RECT 1.000 156.625 4.000 156.765 ;
    END
  END wd_in[5]
  PIN wd_in[6]
    DIRECTION INPUT ;
    USE SIGNAL ;
    PORT
      LAYER metal3 ;
      RECT 1.000 157.780 3.000 157.850 ;
    END
    PORT
      LAYER metal3 ;
      RECT 1.000 157.745 4.000 157.885 ;
    END
  END wd_in[6]
  PIN wd_in[7]
    DIRECTION INPUT ;
    USE SIGNAL ;
    PORT
      LAYER metal3 ;
      RECT 1.000 158.900 3.000 158.970 ;
    END
    PORT
      LAYER metal3 ;
      RECT 1.000 158.865 4.000 159.005 ;
    END
  END wd_in[7]
  PIN wd_in[8]
    DIRECTION INPUT ;
    USE SIGNAL ;
    PORT
      LAYER metal3 ;
      RECT 1.000 160.020 3.000 160.090 ;
    END
    PORT
      LAYER metal3 ;
      RECT 1.000 159.985 4.000 160.125 ;
    END
  END wd_in[8]
  PIN wd_in[9]
    DIRECTION INPUT ;
    USE SIGNAL ;
    PORT
      LAYER metal3 ;
      RECT 1.000 161.140 3.000 161.210 ;
    END
    PORT
      LAYER metal3 ;
      RECT 1.000 161.105 4.000 161.245 ;
    END
  END wd_in[9]
  PIN wd_in[10]
    DIRECTION INPUT ;
    USE SIGNAL ;
    PORT
      LAYER metal3 ;
      RECT 1.000 162.260 3.000 162.330 ;
    END
    PORT
      LAYER metal3 ;
      RECT 1.000 162.225 4.000 162.365 ;
    END
  END wd_in[10]
  PIN wd_in[11]
    DIRECTION INPUT ;
    USE SIGNAL ;
    PORT
      LAYER metal3 ;
      RECT 1.000 163.380 3.000 163.450 ;
    END
    PORT
      LAYER metal3 ;
      RECT 1.000 163.345 4.000 163.485 ;
    END
  END wd_in[11]
  PIN wd_in[12]
    DIRECTION INPUT ;
    USE SIGNAL ;
    PORT
      LAYER metal3 ;
      RECT 1.000 164.500 3.000 164.570 ;
    END
    PORT
      LAYER metal3 ;
      RECT 1.000 164.465 4.000 164.605 ;
    END
  END wd_in[12]
  PIN wd_in[13]
    DIRECTION INPUT ;
    USE SIGNAL ;
    PORT
      LAYER metal3 ;
      RECT 1.000 165.620 3.000 165.690 ;
    END
    PORT
      LAYER metal3 ;
      RECT 1.000 165.585 4.000 165.725 ;
    END
  END wd_in[13]
  PIN wd_in[14]
    DIRECTION INPUT ;
    USE SIGNAL ;
    PORT
      LAYER metal3 ;
      RECT 1.000 166.740 3.000 166.810 ;
    END
    PORT
      LAYER metal3 ;
      RECT 1.000 166.705 4.000 166.845 ;
    END
  END wd_in[14]
  PIN wd_in[15]
    DIRECTION INPUT ;
    USE SIGNAL ;
    PORT
      LAYER metal3 ;
      RECT 1.000 167.860 3.000 167.930 ;
    END
    PORT
      LAYER metal3 ;
      RECT 1.000 167.825 4.000 167.965 ;
    END
  END wd_in[15]
  PIN wd_in[16]
    DIRECTION INPUT ;
    USE SIGNAL ;
    PORT
      LAYER metal3 ;
      RECT 1.000 168.980 3.000 169.050 ;
    END
    PORT
      LAYER metal3 ;
      RECT 1.000 168.945 4.000 169.085 ;
    END
  END wd_in[16]
  PIN wd_in[17]
    DIRECTION INPUT ;
    USE SIGNAL ;
    PORT
      LAYER metal3 ;
      RECT 1.000 170.100 3.000 170.170 ;
    END
    PORT
      LAYER metal3 ;
      RECT 1.000 170.065 4.000 170.205 ;
    END
  END wd_in[17]
  PIN wd_in[18]
    DIRECTION INPUT ;
    USE SIGNAL ;
    PORT
      LAYER metal3 ;
      RECT 1.000 171.220 3.000 171.290 ;
    END
    PORT
      LAYER metal3 ;
      RECT 1.000 171.185 4.000 171.325 ;
    END
  END wd_in[18]
  PIN wd_in[19]
    DIRECTION INPUT ;
    USE SIGNAL ;
    PORT
      LAYER metal3 ;
      RECT 1.000 172.340 3.000 172.410 ;
    END
    PORT
      LAYER metal3 ;
      RECT 1.000 172.305 4.000 172.445 ;
    END
  END wd_in[19]
  PIN wd_in[20]
    DIRECTION INPUT ;
    USE SIGNAL ;
    PORT
      LAYER metal3 ;
      RECT 1.000 173.460 3.000 173.530 ;
    END
    PORT
      LAYER metal3 ;
      RECT 1.000 173.425 4.000 173.565 ;
    END
  END wd_in[20]
  PIN wd_in[21]
    DIRECTION INPUT ;
    USE SIGNAL ;
    PORT
      LAYER metal3 ;
      RECT 1.000 174.580 3.000 174.650 ;
    END
    PORT
      LAYER metal3 ;
      RECT 1.000 174.545 4.000 174.685 ;
    END
  END wd_in[21]
  PIN wd_in[22]
    DIRECTION INPUT ;
    USE SIGNAL ;
    PORT
      LAYER metal3 ;
      RECT 1.000 175.700 3.000 175.770 ;
    END
    PORT
      LAYER metal3 ;
      RECT 1.000 175.665 4.000 175.805 ;
    END
  END wd_in[22]
  PIN wd_in[23]
    DIRECTION INPUT ;
    USE SIGNAL ;
    PORT
      LAYER metal3 ;
      RECT 1.000 176.820 3.000 176.890 ;
    END
    PORT
      LAYER metal3 ;
      RECT 1.000 176.785 4.000 176.925 ;
    END
  END wd_in[23]
  PIN wd_in[24]
    DIRECTION INPUT ;
    USE SIGNAL ;
    PORT
      LAYER metal3 ;
      RECT 1.000 177.940 3.000 178.010 ;
    END
    PORT
      LAYER metal3 ;
      RECT 1.000 177.905 4.000 178.045 ;
    END
  END wd_in[24]
  PIN wd_in[25]
    DIRECTION INPUT ;
    USE SIGNAL ;
    PORT
      LAYER metal3 ;
      RECT 1.000 179.060 3.000 179.130 ;
    END
    PORT
      LAYER metal3 ;
      RECT 1.000 179.025 4.000 179.165 ;
    END
  END wd_in[25]
  PIN wd_in[26]
    DIRECTION INPUT ;
    USE SIGNAL ;
    PORT
      LAYER metal3 ;
      RECT 1.000 180.180 3.000 180.250 ;
    END
    PORT
      LAYER metal3 ;
      RECT 1.000 180.145 4.000 180.285 ;
    END
  END wd_in[26]
  PIN wd_in[27]
    DIRECTION INPUT ;
    USE SIGNAL ;
    PORT
      LAYER metal3 ;
      RECT 1.000 181.300 3.000 181.370 ;
    END
    PORT
      LAYER metal3 ;
      RECT 1.000 181.265 4.000 181.405 ;
    END
  END wd_in[27]
  PIN wd_in[28]
    DIRECTION INPUT ;
    USE SIGNAL ;
    PORT
      LAYER metal3 ;
      RECT 1.000 182.420 3.000 182.490 ;
    END
    PORT
      LAYER metal3 ;
      RECT 1.000 182.385 4.000 182.525 ;
    END
  END wd_in[28]
  PIN wd_in[29]
    DIRECTION INPUT ;
    USE SIGNAL ;
    PORT
      LAYER metal3 ;
      RECT 1.000 183.540 3.000 183.610 ;
    END
    PORT
      LAYER metal3 ;
      RECT 1.000 183.505 4.000 183.645 ;
    END
  END wd_in[29]
  PIN wd_in[30]
    DIRECTION INPUT ;
    USE SIGNAL ;
    PORT
      LAYER metal3 ;
      RECT 1.000 184.660 3.000 184.730 ;
    END
    PORT
      LAYER metal3 ;
      RECT 1.000 184.625 4.000 184.765 ;
    END
  END wd_in[30]
  PIN wd_in[31]
    DIRECTION INPUT ;
    USE SIGNAL ;
    PORT
      LAYER metal3 ;
      RECT 1.000 185.780 3.000 185.850 ;
    END
    PORT
      LAYER metal3 ;
      RECT 1.000 185.745 4.000 185.885 ;
    END
  END wd_in[31]
  PIN wd_in[32]
    DIRECTION INPUT ;
    USE SIGNAL ;
    PORT
      LAYER metal3 ;
      RECT 1.000 186.900 3.000 186.970 ;
    END
    PORT
      LAYER metal3 ;
      RECT 1.000 186.865 4.000 187.005 ;
    END
  END wd_in[32]
  PIN wd_in[33]
    DIRECTION INPUT ;
    USE SIGNAL ;
    PORT
      LAYER metal3 ;
      RECT 1.000 188.020 3.000 188.090 ;
    END
    PORT
      LAYER metal3 ;
      RECT 1.000 187.985 4.000 188.125 ;
    END
  END wd_in[33]
  PIN wd_in[34]
    DIRECTION INPUT ;
    USE SIGNAL ;
    PORT
      LAYER metal3 ;
      RECT 1.000 189.140 3.000 189.210 ;
    END
    PORT
      LAYER metal3 ;
      RECT 1.000 189.105 4.000 189.245 ;
    END
  END wd_in[34]
  PIN wd_in[35]
    DIRECTION INPUT ;
    USE SIGNAL ;
    PORT
      LAYER metal3 ;
      RECT 1.000 190.260 3.000 190.330 ;
    END
    PORT
      LAYER metal3 ;
      RECT 1.000 190.225 4.000 190.365 ;
    END
  END wd_in[35]
  PIN wd_in[36]
    DIRECTION INPUT ;
    USE SIGNAL ;
    PORT
      LAYER metal3 ;
      RECT 1.000 191.380 3.000 191.450 ;
    END
    PORT
      LAYER metal3 ;
      RECT 1.000 191.345 4.000 191.485 ;
    END
  END wd_in[36]
  PIN wd_in[37]
    DIRECTION INPUT ;
    USE SIGNAL ;
    PORT
      LAYER metal3 ;
      RECT 1.000 192.500 3.000 192.570 ;
    END
    PORT
      LAYER metal3 ;
      RECT 1.000 192.465 4.000 192.605 ;
    END
  END wd_in[37]
  PIN wd_in[38]
    DIRECTION INPUT ;
    USE SIGNAL ;
    PORT
      LAYER metal3 ;
      RECT 1.000 193.620 3.000 193.690 ;
    END
    PORT
      LAYER metal3 ;
      RECT 1.000 193.585 4.000 193.725 ;
    END
  END wd_in[38]
  PIN wd_in[39]
    DIRECTION INPUT ;
    USE SIGNAL ;
    PORT
      LAYER metal3 ;
      RECT 1.000 194.740 3.000 194.810 ;
    END
    PORT
      LAYER metal3 ;
      RECT 1.000 194.705 4.000 194.845 ;
    END
  END wd_in[39]
  PIN wd_in[40]
    DIRECTION INPUT ;
    USE SIGNAL ;
    PORT
      LAYER metal3 ;
      RECT 1.000 195.860 3.000 195.930 ;
    END
    PORT
      LAYER metal3 ;
      RECT 1.000 195.825 4.000 195.965 ;
    END
  END wd_in[40]
  PIN wd_in[41]
    DIRECTION INPUT ;
    USE SIGNAL ;
    PORT
      LAYER metal3 ;
      RECT 1.000 196.980 3.000 197.050 ;
    END
    PORT
      LAYER metal3 ;
      RECT 1.000 196.945 4.000 197.085 ;
    END
  END wd_in[41]
  PIN wd_in[42]
    DIRECTION INPUT ;
    USE SIGNAL ;
    PORT
      LAYER metal3 ;
      RECT 1.000 198.100 3.000 198.170 ;
    END
    PORT
      LAYER metal3 ;
      RECT 1.000 198.065 4.000 198.205 ;
    END
  END wd_in[42]
  PIN wd_in[43]
    DIRECTION INPUT ;
    USE SIGNAL ;
    PORT
      LAYER metal3 ;
      RECT 1.000 199.220 3.000 199.290 ;
    END
    PORT
      LAYER metal3 ;
      RECT 1.000 199.185 4.000 199.325 ;
    END
  END wd_in[43]
  PIN wd_in[44]
    DIRECTION INPUT ;
    USE SIGNAL ;
    PORT
      LAYER metal3 ;
      RECT 1.000 200.340 3.000 200.410 ;
    END
    PORT
      LAYER metal3 ;
      RECT 1.000 200.305 4.000 200.445 ;
    END
  END wd_in[44]
  PIN wd_in[45]
    DIRECTION INPUT ;
    USE SIGNAL ;
    PORT
      LAYER metal3 ;
      RECT 1.000 201.460 3.000 201.530 ;
    END
    PORT
      LAYER metal3 ;
      RECT 1.000 201.425 4.000 201.565 ;
    END
  END wd_in[45]
  PIN wd_in[46]
    DIRECTION INPUT ;
    USE SIGNAL ;
    PORT
      LAYER metal3 ;
      RECT 1.000 202.580 3.000 202.650 ;
    END
    PORT
      LAYER metal3 ;
      RECT 1.000 202.545 4.000 202.685 ;
    END
  END wd_in[46]
  PIN wd_in[47]
    DIRECTION INPUT ;
    USE SIGNAL ;
    PORT
      LAYER metal3 ;
      RECT 1.000 203.700 3.000 203.770 ;
    END
    PORT
      LAYER metal3 ;
      RECT 1.000 203.665 4.000 203.805 ;
    END
  END wd_in[47]
  PIN wd_in[48]
    DIRECTION INPUT ;
    USE SIGNAL ;
    PORT
      LAYER metal3 ;
      RECT 1.000 204.820 3.000 204.890 ;
    END
    PORT
      LAYER metal3 ;
      RECT 1.000 204.785 4.000 204.925 ;
    END
  END wd_in[48]
  PIN wd_in[49]
    DIRECTION INPUT ;
    USE SIGNAL ;
    PORT
      LAYER metal3 ;
      RECT 1.000 205.940 3.000 206.010 ;
    END
    PORT
      LAYER metal3 ;
      RECT 1.000 205.905 4.000 206.045 ;
    END
  END wd_in[49]
  PIN wd_in[50]
    DIRECTION INPUT ;
    USE SIGNAL ;
    PORT
      LAYER metal3 ;
      RECT 1.000 207.060 3.000 207.130 ;
    END
    PORT
      LAYER metal3 ;
      RECT 1.000 207.025 4.000 207.165 ;
    END
  END wd_in[50]
  PIN wd_in[51]
    DIRECTION INPUT ;
    USE SIGNAL ;
    PORT
      LAYER metal3 ;
      RECT 1.000 208.180 3.000 208.250 ;
    END
    PORT
      LAYER metal3 ;
      RECT 1.000 208.145 4.000 208.285 ;
    END
  END wd_in[51]
  PIN wd_in[52]
    DIRECTION INPUT ;
    USE SIGNAL ;
    PORT
      LAYER metal3 ;
      RECT 1.000 209.300 3.000 209.370 ;
    END
    PORT
      LAYER metal3 ;
      RECT 1.000 209.265 4.000 209.405 ;
    END
  END wd_in[52]
  PIN wd_in[53]
    DIRECTION INPUT ;
    USE SIGNAL ;
    PORT
      LAYER metal3 ;
      RECT 1.000 210.420 3.000 210.490 ;
    END
    PORT
      LAYER metal3 ;
      RECT 1.000 210.385 4.000 210.525 ;
    END
  END wd_in[53]
  PIN wd_in[54]
    DIRECTION INPUT ;
    USE SIGNAL ;
    PORT
      LAYER metal3 ;
      RECT 1.000 211.540 3.000 211.610 ;
    END
    PORT
      LAYER metal3 ;
      RECT 1.000 211.505 4.000 211.645 ;
    END
  END wd_in[54]
  PIN wd_in[55]
    DIRECTION INPUT ;
    USE SIGNAL ;
    PORT
      LAYER metal3 ;
      RECT 1.000 212.660 3.000 212.730 ;
    END
    PORT
      LAYER metal3 ;
      RECT 1.000 212.625 4.000 212.765 ;
    END
  END wd_in[55]
  PIN wd_in[56]
    DIRECTION INPUT ;
    USE SIGNAL ;
    PORT
      LAYER metal3 ;
      RECT 1.000 213.780 3.000 213.850 ;
    END
    PORT
      LAYER metal3 ;
      RECT 1.000 213.745 4.000 213.885 ;
    END
  END wd_in[56]
  PIN wd_in[57]
    DIRECTION INPUT ;
    USE SIGNAL ;
    PORT
      LAYER metal3 ;
      RECT 1.000 214.900 3.000 214.970 ;
    END
    PORT
      LAYER metal3 ;
      RECT 1.000 214.865 4.000 215.005 ;
    END
  END wd_in[57]
  PIN wd_in[58]
    DIRECTION INPUT ;
    USE SIGNAL ;
    PORT
      LAYER metal3 ;
      RECT 1.000 216.020 3.000 216.090 ;
    END
    PORT
      LAYER metal3 ;
      RECT 1.000 215.985 4.000 216.125 ;
    END
  END wd_in[58]
  PIN wd_in[59]
    DIRECTION INPUT ;
    USE SIGNAL ;
    PORT
      LAYER metal3 ;
      RECT 1.000 217.140 3.000 217.210 ;
    END
    PORT
      LAYER metal3 ;
      RECT 1.000 217.105 4.000 217.245 ;
    END
  END wd_in[59]
  PIN wd_in[60]
    DIRECTION INPUT ;
    USE SIGNAL ;
    PORT
      LAYER metal3 ;
      RECT 1.000 218.260 3.000 218.330 ;
    END
    PORT
      LAYER metal3 ;
      RECT 1.000 218.225 4.000 218.365 ;
    END
  END wd_in[60]
  PIN wd_in[61]
    DIRECTION INPUT ;
    USE SIGNAL ;
    PORT
      LAYER metal3 ;
      RECT 1.000 219.380 3.000 219.450 ;
    END
    PORT
      LAYER metal3 ;
      RECT 1.000 219.345 4.000 219.485 ;
    END
  END wd_in[61]
  PIN wd_in[62]
    DIRECTION INPUT ;
    USE SIGNAL ;
    PORT
      LAYER metal3 ;
      RECT 1.000 220.500 3.000 220.570 ;
    END
    PORT
      LAYER metal3 ;
      RECT 1.000 220.465 4.000 220.605 ;
    END
  END wd_in[62]
  PIN wd_in[63]
    DIRECTION INPUT ;
    USE SIGNAL ;
    PORT
      LAYER metal3 ;
      RECT 1.000 221.620 3.000 221.690 ;
    END
    PORT
      LAYER metal3 ;
      RECT 1.000 221.585 4.000 221.725 ;
    END
  END wd_in[63]
  PIN wd_in[64]
    DIRECTION INPUT ;
    USE SIGNAL ;
    PORT
      LAYER metal3 ;
      RECT 1.000 222.740 3.000 222.810 ;
    END
    PORT
      LAYER metal3 ;
      RECT 1.000 222.705 4.000 222.845 ;
    END
  END wd_in[64]
  PIN wd_in[65]
    DIRECTION INPUT ;
    USE SIGNAL ;
    PORT
      LAYER metal3 ;
      RECT 1.000 223.860 3.000 223.930 ;
    END
    PORT
      LAYER metal3 ;
      RECT 1.000 223.825 4.000 223.965 ;
    END
  END wd_in[65]
  PIN wd_in[66]
    DIRECTION INPUT ;
    USE SIGNAL ;
    PORT
      LAYER metal3 ;
      RECT 1.000 224.980 3.000 225.050 ;
    END
    PORT
      LAYER metal3 ;
      RECT 1.000 224.945 4.000 225.085 ;
    END
  END wd_in[66]
  PIN wd_in[67]
    DIRECTION INPUT ;
    USE SIGNAL ;
    PORT
      LAYER metal3 ;
      RECT 1.000 226.100 3.000 226.170 ;
    END
    PORT
      LAYER metal3 ;
      RECT 1.000 226.065 4.000 226.205 ;
    END
  END wd_in[67]
  PIN wd_in[68]
    DIRECTION INPUT ;
    USE SIGNAL ;
    PORT
      LAYER metal3 ;
      RECT 1.000 227.220 3.000 227.290 ;
    END
    PORT
      LAYER metal3 ;
      RECT 1.000 227.185 4.000 227.325 ;
    END
  END wd_in[68]
  PIN wd_in[69]
    DIRECTION INPUT ;
    USE SIGNAL ;
    PORT
      LAYER metal3 ;
      RECT 1.000 228.340 3.000 228.410 ;
    END
    PORT
      LAYER metal3 ;
      RECT 1.000 228.305 4.000 228.445 ;
    END
  END wd_in[69]
  PIN wd_in[70]
    DIRECTION INPUT ;
    USE SIGNAL ;
    PORT
      LAYER metal3 ;
      RECT 1.000 229.460 3.000 229.530 ;
    END
    PORT
      LAYER metal3 ;
      RECT 1.000 229.425 4.000 229.565 ;
    END
  END wd_in[70]
  PIN wd_in[71]
    DIRECTION INPUT ;
    USE SIGNAL ;
    PORT
      LAYER metal3 ;
      RECT 1.000 230.580 3.000 230.650 ;
    END
    PORT
      LAYER metal3 ;
      RECT 1.000 230.545 4.000 230.685 ;
    END
  END wd_in[71]
  PIN wd_in[72]
    DIRECTION INPUT ;
    USE SIGNAL ;
    PORT
      LAYER metal3 ;
      RECT 1.000 231.700 3.000 231.770 ;
    END
    PORT
      LAYER metal3 ;
      RECT 1.000 231.665 4.000 231.805 ;
    END
  END wd_in[72]
  PIN wd_in[73]
    DIRECTION INPUT ;
    USE SIGNAL ;
    PORT
      LAYER metal3 ;
      RECT 1.000 232.820 3.000 232.890 ;
    END
    PORT
      LAYER metal3 ;
      RECT 1.000 232.785 4.000 232.925 ;
    END
  END wd_in[73]
  PIN wd_in[74]
    DIRECTION INPUT ;
    USE SIGNAL ;
    PORT
      LAYER metal3 ;
      RECT 1.000 233.940 3.000 234.010 ;
    END
    PORT
      LAYER metal3 ;
      RECT 1.000 233.905 4.000 234.045 ;
    END
  END wd_in[74]
  PIN wd_in[75]
    DIRECTION INPUT ;
    USE SIGNAL ;
    PORT
      LAYER metal3 ;
      RECT 1.000 235.060 3.000 235.130 ;
    END
    PORT
      LAYER metal3 ;
      RECT 1.000 235.025 4.000 235.165 ;
    END
  END wd_in[75]
  PIN wd_in[76]
    DIRECTION INPUT ;
    USE SIGNAL ;
    PORT
      LAYER metal3 ;
      RECT 1.000 236.180 3.000 236.250 ;
    END
    PORT
      LAYER metal3 ;
      RECT 1.000 236.145 4.000 236.285 ;
    END
  END wd_in[76]
  PIN wd_in[77]
    DIRECTION INPUT ;
    USE SIGNAL ;
    PORT
      LAYER metal3 ;
      RECT 1.000 237.300 3.000 237.370 ;
    END
    PORT
      LAYER metal3 ;
      RECT 1.000 237.265 4.000 237.405 ;
    END
  END wd_in[77]
  PIN wd_in[78]
    DIRECTION INPUT ;
    USE SIGNAL ;
    PORT
      LAYER metal3 ;
      RECT 1.000 238.420 3.000 238.490 ;
    END
    PORT
      LAYER metal3 ;
      RECT 1.000 238.385 4.000 238.525 ;
    END
  END wd_in[78]
  PIN wd_in[79]
    DIRECTION INPUT ;
    USE SIGNAL ;
    PORT
      LAYER metal3 ;
      RECT 1.000 239.540 3.000 239.610 ;
    END
    PORT
      LAYER metal3 ;
      RECT 1.000 239.505 4.000 239.645 ;
    END
  END wd_in[79]
  PIN wd_in[80]
    DIRECTION INPUT ;
    USE SIGNAL ;
    PORT
      LAYER metal3 ;
      RECT 1.000 240.660 3.000 240.730 ;
    END
    PORT
      LAYER metal3 ;
      RECT 1.000 240.625 4.000 240.765 ;
    END
  END wd_in[80]
  PIN wd_in[81]
    DIRECTION INPUT ;
    USE SIGNAL ;
    PORT
      LAYER metal3 ;
      RECT 1.000 241.780 3.000 241.850 ;
    END
    PORT
      LAYER metal3 ;
      RECT 1.000 241.745 4.000 241.885 ;
    END
  END wd_in[81]
  PIN wd_in[82]
    DIRECTION INPUT ;
    USE SIGNAL ;
    PORT
      LAYER metal3 ;
      RECT 1.000 242.900 3.000 242.970 ;
    END
    PORT
      LAYER metal3 ;
      RECT 1.000 242.865 4.000 243.005 ;
    END
  END wd_in[82]
  PIN wd_in[83]
    DIRECTION INPUT ;
    USE SIGNAL ;
    PORT
      LAYER metal3 ;
      RECT 1.000 244.020 3.000 244.090 ;
    END
    PORT
      LAYER metal3 ;
      RECT 1.000 243.985 4.000 244.125 ;
    END
  END wd_in[83]
  PIN wd_in[84]
    DIRECTION INPUT ;
    USE SIGNAL ;
    PORT
      LAYER metal3 ;
      RECT 1.000 245.140 3.000 245.210 ;
    END
    PORT
      LAYER metal3 ;
      RECT 1.000 245.105 4.000 245.245 ;
    END
  END wd_in[84]
  PIN wd_in[85]
    DIRECTION INPUT ;
    USE SIGNAL ;
    PORT
      LAYER metal3 ;
      RECT 1.000 246.260 3.000 246.330 ;
    END
    PORT
      LAYER metal3 ;
      RECT 1.000 246.225 4.000 246.365 ;
    END
  END wd_in[85]
  PIN wd_in[86]
    DIRECTION INPUT ;
    USE SIGNAL ;
    PORT
      LAYER metal3 ;
      RECT 1.000 247.380 3.000 247.450 ;
    END
    PORT
      LAYER metal3 ;
      RECT 1.000 247.345 4.000 247.485 ;
    END
  END wd_in[86]
  PIN wd_in[87]
    DIRECTION INPUT ;
    USE SIGNAL ;
    PORT
      LAYER metal3 ;
      RECT 1.000 248.500 3.000 248.570 ;
    END
    PORT
      LAYER metal3 ;
      RECT 1.000 248.465 4.000 248.605 ;
    END
  END wd_in[87]
  PIN wd_in[88]
    DIRECTION INPUT ;
    USE SIGNAL ;
    PORT
      LAYER metal3 ;
      RECT 1.000 249.620 3.000 249.690 ;
    END
    PORT
      LAYER metal3 ;
      RECT 1.000 249.585 4.000 249.725 ;
    END
  END wd_in[88]
  PIN wd_in[89]
    DIRECTION INPUT ;
    USE SIGNAL ;
    PORT
      LAYER metal3 ;
      RECT 1.000 250.740 3.000 250.810 ;
    END
    PORT
      LAYER metal3 ;
      RECT 1.000 250.705 4.000 250.845 ;
    END
  END wd_in[89]
  PIN wd_in[90]
    DIRECTION INPUT ;
    USE SIGNAL ;
    PORT
      LAYER metal3 ;
      RECT 1.000 251.860 3.000 251.930 ;
    END
    PORT
      LAYER metal3 ;
      RECT 1.000 251.825 4.000 251.965 ;
    END
  END wd_in[90]
  PIN wd_in[91]
    DIRECTION INPUT ;
    USE SIGNAL ;
    PORT
      LAYER metal3 ;
      RECT 1.000 252.980 3.000 253.050 ;
    END
    PORT
      LAYER metal3 ;
      RECT 1.000 252.945 4.000 253.085 ;
    END
  END wd_in[91]
  PIN wd_in[92]
    DIRECTION INPUT ;
    USE SIGNAL ;
    PORT
      LAYER metal3 ;
      RECT 1.000 254.100 3.000 254.170 ;
    END
    PORT
      LAYER metal3 ;
      RECT 1.000 254.065 4.000 254.205 ;
    END
  END wd_in[92]
  PIN wd_in[93]
    DIRECTION INPUT ;
    USE SIGNAL ;
    PORT
      LAYER metal3 ;
      RECT 1.000 255.220 3.000 255.290 ;
    END
    PORT
      LAYER metal3 ;
      RECT 1.000 255.185 4.000 255.325 ;
    END
  END wd_in[93]
  PIN wd_in[94]
    DIRECTION INPUT ;
    USE SIGNAL ;
    PORT
      LAYER metal3 ;
      RECT 1.000 256.340 3.000 256.410 ;
    END
    PORT
      LAYER metal3 ;
      RECT 1.000 256.305 4.000 256.445 ;
    END
  END wd_in[94]
  PIN wd_in[95]
    DIRECTION INPUT ;
    USE SIGNAL ;
    PORT
      LAYER metal3 ;
      RECT 1.000 257.460 3.000 257.530 ;
    END
    PORT
      LAYER metal3 ;
      RECT 1.000 257.425 4.000 257.565 ;
    END
  END wd_in[95]
  PIN wd_in[96]
    DIRECTION INPUT ;
    USE SIGNAL ;
    PORT
      LAYER metal3 ;
      RECT 1.000 258.580 3.000 258.650 ;
    END
    PORT
      LAYER metal3 ;
      RECT 1.000 258.545 4.000 258.685 ;
    END
  END wd_in[96]
  PIN wd_in[97]
    DIRECTION INPUT ;
    USE SIGNAL ;
    PORT
      LAYER metal3 ;
      RECT 1.000 259.700 3.000 259.770 ;
    END
    PORT
      LAYER metal3 ;
      RECT 1.000 259.665 4.000 259.805 ;
    END
  END wd_in[97]
  PIN wd_in[98]
    DIRECTION INPUT ;
    USE SIGNAL ;
    PORT
      LAYER metal3 ;
      RECT 1.000 260.820 3.000 260.890 ;
    END
    PORT
      LAYER metal3 ;
      RECT 1.000 260.785 4.000 260.925 ;
    END
  END wd_in[98]
  PIN wd_in[99]
    DIRECTION INPUT ;
    USE SIGNAL ;
    PORT
      LAYER metal3 ;
      RECT 1.000 261.940 3.000 262.010 ;
    END
    PORT
      LAYER metal3 ;
      RECT 1.000 261.905 4.000 262.045 ;
    END
  END wd_in[99]
  PIN wd_in[100]
    DIRECTION INPUT ;
    USE SIGNAL ;
    PORT
      LAYER metal3 ;
      RECT 1.000 263.060 3.000 263.130 ;
    END
    PORT
      LAYER metal3 ;
      RECT 1.000 263.025 4.000 263.165 ;
    END
  END wd_in[100]
  PIN wd_in[101]
    DIRECTION INPUT ;
    USE SIGNAL ;
    PORT
      LAYER metal3 ;
      RECT 1.000 264.180 3.000 264.250 ;
    END
    PORT
      LAYER metal3 ;
      RECT 1.000 264.145 4.000 264.285 ;
    END
  END wd_in[101]
  PIN wd_in[102]
    DIRECTION INPUT ;
    USE SIGNAL ;
    PORT
      LAYER metal3 ;
      RECT 1.000 265.300 3.000 265.370 ;
    END
    PORT
      LAYER metal3 ;
      RECT 1.000 265.265 4.000 265.405 ;
    END
  END wd_in[102]
  PIN wd_in[103]
    DIRECTION INPUT ;
    USE SIGNAL ;
    PORT
      LAYER metal3 ;
      RECT 1.000 266.420 3.000 266.490 ;
    END
    PORT
      LAYER metal3 ;
      RECT 1.000 266.385 4.000 266.525 ;
    END
  END wd_in[103]
  PIN wd_in[104]
    DIRECTION INPUT ;
    USE SIGNAL ;
    PORT
      LAYER metal3 ;
      RECT 1.000 267.540 3.000 267.610 ;
    END
    PORT
      LAYER metal3 ;
      RECT 1.000 267.505 4.000 267.645 ;
    END
  END wd_in[104]
  PIN wd_in[105]
    DIRECTION INPUT ;
    USE SIGNAL ;
    PORT
      LAYER metal3 ;
      RECT 1.000 268.660 3.000 268.730 ;
    END
    PORT
      LAYER metal3 ;
      RECT 1.000 268.625 4.000 268.765 ;
    END
  END wd_in[105]
  PIN wd_in[106]
    DIRECTION INPUT ;
    USE SIGNAL ;
    PORT
      LAYER metal3 ;
      RECT 1.000 269.780 3.000 269.850 ;
    END
    PORT
      LAYER metal3 ;
      RECT 1.000 269.745 4.000 269.885 ;
    END
  END wd_in[106]
  PIN wd_in[107]
    DIRECTION INPUT ;
    USE SIGNAL ;
    PORT
      LAYER metal3 ;
      RECT 1.000 270.900 3.000 270.970 ;
    END
    PORT
      LAYER metal3 ;
      RECT 1.000 270.865 4.000 271.005 ;
    END
  END wd_in[107]
  PIN wd_in[108]
    DIRECTION INPUT ;
    USE SIGNAL ;
    PORT
      LAYER metal3 ;
      RECT 1.000 272.020 3.000 272.090 ;
    END
    PORT
      LAYER metal3 ;
      RECT 1.000 271.985 4.000 272.125 ;
    END
  END wd_in[108]
  PIN wd_in[109]
    DIRECTION INPUT ;
    USE SIGNAL ;
    PORT
      LAYER metal3 ;
      RECT 1.000 273.140 3.000 273.210 ;
    END
    PORT
      LAYER metal3 ;
      RECT 1.000 273.105 4.000 273.245 ;
    END
  END wd_in[109]
  PIN wd_in[110]
    DIRECTION INPUT ;
    USE SIGNAL ;
    PORT
      LAYER metal3 ;
      RECT 1.000 274.260 3.000 274.330 ;
    END
    PORT
      LAYER metal3 ;
      RECT 1.000 274.225 4.000 274.365 ;
    END
  END wd_in[110]
  PIN wd_in[111]
    DIRECTION INPUT ;
    USE SIGNAL ;
    PORT
      LAYER metal3 ;
      RECT 1.000 275.380 3.000 275.450 ;
    END
    PORT
      LAYER metal3 ;
      RECT 1.000 275.345 4.000 275.485 ;
    END
  END wd_in[111]
  PIN wd_in[112]
    DIRECTION INPUT ;
    USE SIGNAL ;
    PORT
      LAYER metal3 ;
      RECT 1.000 276.500 3.000 276.570 ;
    END
    PORT
      LAYER metal3 ;
      RECT 1.000 276.465 4.000 276.605 ;
    END
  END wd_in[112]
  PIN wd_in[113]
    DIRECTION INPUT ;
    USE SIGNAL ;
    PORT
      LAYER metal3 ;
      RECT 1.000 277.620 3.000 277.690 ;
    END
    PORT
      LAYER metal3 ;
      RECT 1.000 277.585 4.000 277.725 ;
    END
  END wd_in[113]
  PIN wd_in[114]
    DIRECTION INPUT ;
    USE SIGNAL ;
    PORT
      LAYER metal3 ;
      RECT 1.000 278.740 3.000 278.810 ;
    END
    PORT
      LAYER metal3 ;
      RECT 1.000 278.705 4.000 278.845 ;
    END
  END wd_in[114]
  PIN wd_in[115]
    DIRECTION INPUT ;
    USE SIGNAL ;
    PORT
      LAYER metal3 ;
      RECT 1.000 279.860 3.000 279.930 ;
    END
    PORT
      LAYER metal3 ;
      RECT 1.000 279.825 4.000 279.965 ;
    END
  END wd_in[115]
  PIN wd_in[116]
    DIRECTION INPUT ;
    USE SIGNAL ;
    PORT
      LAYER metal3 ;
      RECT 1.000 280.980 3.000 281.050 ;
    END
    PORT
      LAYER metal3 ;
      RECT 1.000 280.945 4.000 281.085 ;
    END
  END wd_in[116]
  PIN wd_in[117]
    DIRECTION INPUT ;
    USE SIGNAL ;
    PORT
      LAYER metal3 ;
      RECT 1.000 282.100 3.000 282.170 ;
    END
    PORT
      LAYER metal3 ;
      RECT 1.000 282.065 4.000 282.205 ;
    END
  END wd_in[117]
  PIN wd_in[118]
    DIRECTION INPUT ;
    USE SIGNAL ;
    PORT
      LAYER metal3 ;
      RECT 1.000 283.220 3.000 283.290 ;
    END
    PORT
      LAYER metal3 ;
      RECT 1.000 283.185 4.000 283.325 ;
    END
  END wd_in[118]
  PIN wd_in[119]
    DIRECTION INPUT ;
    USE SIGNAL ;
    PORT
      LAYER metal3 ;
      RECT 1.000 284.340 3.000 284.410 ;
    END
    PORT
      LAYER metal3 ;
      RECT 1.000 284.305 4.000 284.445 ;
    END
  END wd_in[119]
  PIN wd_in[120]
    DIRECTION INPUT ;
    USE SIGNAL ;
    PORT
      LAYER metal3 ;
      RECT 1.000 285.460 3.000 285.530 ;
    END
    PORT
      LAYER metal3 ;
      RECT 1.000 285.425 4.000 285.565 ;
    END
  END wd_in[120]
  PIN wd_in[121]
    DIRECTION INPUT ;
    USE SIGNAL ;
    PORT
      LAYER metal3 ;
      RECT 1.000 286.580 3.000 286.650 ;
    END
    PORT
      LAYER metal3 ;
      RECT 1.000 286.545 4.000 286.685 ;
    END
  END wd_in[121]
  PIN wd_in[122]
    DIRECTION INPUT ;
    USE SIGNAL ;
    PORT
      LAYER metal3 ;
      RECT 1.000 287.700 3.000 287.770 ;
    END
    PORT
      LAYER metal3 ;
      RECT 1.000 287.665 4.000 287.805 ;
    END
  END wd_in[122]
  PIN wd_in[123]
    DIRECTION INPUT ;
    USE SIGNAL ;
    PORT
      LAYER metal3 ;
      RECT 1.000 288.820 3.000 288.890 ;
    END
    PORT
      LAYER metal3 ;
      RECT 1.000 288.785 4.000 288.925 ;
    END
  END wd_in[123]
  PIN wd_in[124]
    DIRECTION INPUT ;
    USE SIGNAL ;
    PORT
      LAYER metal3 ;
      RECT 1.000 289.940 3.000 290.010 ;
    END
    PORT
      LAYER metal3 ;
      RECT 1.000 289.905 4.000 290.045 ;
    END
  END wd_in[124]
  PIN wd_in[125]
    DIRECTION INPUT ;
    USE SIGNAL ;
    PORT
      LAYER metal3 ;
      RECT 1.000 291.060 3.000 291.130 ;
    END
    PORT
      LAYER metal3 ;
      RECT 1.000 291.025 4.000 291.165 ;
    END
  END wd_in[125]
  PIN wd_in[126]
    DIRECTION INPUT ;
    USE SIGNAL ;
    PORT
      LAYER metal3 ;
      RECT 1.000 292.180 3.000 292.250 ;
    END
    PORT
      LAYER metal3 ;
      RECT 1.000 292.145 4.000 292.285 ;
    END
  END wd_in[126]
  PIN wd_in[127]
    DIRECTION INPUT ;
    USE SIGNAL ;
    PORT
      LAYER metal3 ;
      RECT 1.000 293.300 3.000 293.370 ;
    END
    PORT
      LAYER metal3 ;
      RECT 1.000 293.265 4.000 293.405 ;
    END
  END wd_in[127]
  PIN addr_in[0]
    DIRECTION INPUT ;
    USE SIGNAL ;
    PORT
      LAYER metal3 ;
      RECT 1.000 301.980 3.000 302.050 ;
    END
    PORT
      LAYER metal3 ;
      RECT 1.000 301.945 4.000 302.085 ;
    END
  END addr_in[0]
  PIN addr_in[1]
    DIRECTION INPUT ;
    USE SIGNAL ;
    PORT
      LAYER metal3 ;
      RECT 1.000 303.100 3.000 303.170 ;
    END
    PORT
      LAYER metal3 ;
      RECT 1.000 303.065 4.000 303.205 ;
    END
  END addr_in[1]
  PIN addr_in[2]
    DIRECTION INPUT ;
    USE SIGNAL ;
    PORT
      LAYER metal3 ;
      RECT 1.000 304.220 3.000 304.290 ;
    END
    PORT
      LAYER metal3 ;
      RECT 1.000 304.185 4.000 304.325 ;
    END
  END addr_in[2]
  PIN addr_in[3]
    DIRECTION INPUT ;
    USE SIGNAL ;
    PORT
      LAYER metal3 ;
      RECT 1.000 305.340 3.000 305.410 ;
    END
    PORT
      LAYER metal3 ;
      RECT 1.000 305.305 4.000 305.445 ;
    END
  END addr_in[3]
  PIN addr_in[4]
    DIRECTION INPUT ;
    USE SIGNAL ;
    PORT
      LAYER metal3 ;
      RECT 1.000 306.460 3.000 306.530 ;
    END
    PORT
      LAYER metal3 ;
      RECT 1.000 306.425 4.000 306.565 ;
    END
  END addr_in[4]
  PIN addr_in[5]
    DIRECTION INPUT ;
    USE SIGNAL ;
    PORT
      LAYER metal3 ;
      RECT 1.000 307.580 3.000 307.650 ;
    END
    PORT
      LAYER metal3 ;
      RECT 1.000 307.545 4.000 307.685 ;
    END
  END addr_in[5]
  PIN addr_in[6]
    DIRECTION INPUT ;
    USE SIGNAL ;
    PORT
      LAYER metal3 ;
      RECT 1.000 308.700 3.000 308.770 ;
    END
    PORT
      LAYER metal3 ;
      RECT 1.000 308.665 4.000 308.805 ;
    END
  END addr_in[6]
  PIN addr_in[7]
    DIRECTION INPUT ;
    USE SIGNAL ;
    PORT
      LAYER metal3 ;
      RECT 1.000 309.820 3.000 309.890 ;
    END
    PORT
      LAYER metal3 ;
      RECT 1.000 309.785 4.000 309.925 ;
    END
  END addr_in[7]
  PIN addr_in[8]
    DIRECTION INPUT ;
    USE SIGNAL ;
    PORT
      LAYER metal3 ;
      RECT 1.000 310.940 3.000 311.010 ;
    END
    PORT
      LAYER metal3 ;
      RECT 1.000 310.905 4.000 311.045 ;
    END
  END addr_in[8]
  PIN we_in
    DIRECTION INPUT ;
    USE SIGNAL ;
    PORT
      LAYER metal3 ;
      RECT 1.000 319.620 3.000 319.690 ;
    END
    PORT
      LAYER metal3 ;
      RECT 1.000 319.585 4.000 319.725 ;
    END
  END we_in
  PIN ce_in
    DIRECTION INPUT ;
    USE SIGNAL ;
    PORT
      LAYER metal3 ;
      RECT 1.000 320.740 3.000 320.810 ;
    END
    PORT
      LAYER metal3 ;
      RECT 1.000 320.705 4.000 320.845 ;
    END
  END ce_in
  PIN clk
    DIRECTION INPUT ;
    USE SIGNAL ;
    PORT
      LAYER metal3 ;
      RECT 1.000 321.860 3.000 321.930 ;
    END
    PORT
      LAYER metal3 ;
      RECT 1.000 321.825 4.000 321.965 ;
    END
  END clk
  PIN VSS
    DIRECTION INOUT ;
    USE GROUND ;
    PORT
      LAYER metal3 ;
      RECT 0.140 0.000 258.020 0.280 ;
      RECT 0.140 2.240 258.020 2.520 ;
      RECT 0.140 4.480 258.020 4.760 ;
      RECT 0.140 6.720 258.020 7.000 ;
      RECT 0.140 8.960 258.020 9.240 ;
      RECT 0.140 11.200 258.020 11.480 ;
      RECT 0.140 13.440 258.020 13.720 ;
      RECT 0.140 15.680 258.020 15.960 ;
      RECT 0.140 17.920 258.020 18.200 ;
      RECT 0.140 20.160 258.020 20.440 ;
      RECT 0.140 22.400 258.020 22.680 ;
      RECT 0.140 24.640 258.020 24.920 ;
      RECT 0.140 26.880 258.020 27.160 ;
      RECT 0.140 29.120 258.020 29.400 ;
      RECT 0.140 31.360 258.020 31.640 ;
      RECT 0.140 33.600 258.020 33.880 ;
      RECT 0.140 35.840 258.020 36.120 ;
      RECT 0.140 38.080 258.020 38.360 ;
      RECT 0.140 40.320 258.020 40.600 ;
      RECT 0.140 42.560 258.020 42.840 ;
      RECT 0.140 44.800 258.020 45.080 ;
      RECT 0.140 47.040 258.020 47.320 ;
      RECT 0.140 49.280 258.020 49.560 ;
      RECT 0.140 51.520 258.020 51.800 ;
      RECT 0.140 53.760 258.020 54.040 ;
      RECT 0.140 56.000 258.020 56.280 ;
      RECT 0.140 58.240 258.020 58.520 ;
      RECT 0.140 60.480 258.020 60.760 ;
      RECT 0.140 62.720 258.020 63.000 ;
      RECT 0.140 64.960 258.020 65.240 ;
      RECT 0.140 67.200 258.020 67.480 ;
      RECT 0.140 69.440 258.020 69.720 ;
      RECT 0.140 71.680 258.020 71.960 ;
      RECT 0.140 73.920 258.020 74.200 ;
      RECT 0.140 76.160 258.020 76.440 ;
      RECT 0.140 78.400 258.020 78.680 ;
      RECT 0.140 80.640 258.020 80.920 ;
      RECT 0.140 82.880 258.020 83.160 ;
      RECT 0.140 85.120 258.020 85.400 ;
      RECT 0.140 87.360 258.020 87.640 ;
      RECT 0.140 89.600 258.020 89.880 ;
      RECT 0.140 91.840 258.020 92.120 ;
      RECT 0.140 94.080 258.020 94.360 ;
      RECT 0.140 96.320 258.020 96.600 ;
      RECT 0.140 98.560 258.020 98.840 ;
      RECT 0.140 100.800 258.020 101.080 ;
      RECT 0.140 103.040 258.020 103.320 ;
      RECT 0.140 105.280 258.020 105.560 ;
      RECT 0.140 107.520 258.020 107.800 ;
      RECT 0.140 109.760 258.020 110.040 ;
      RECT 0.140 112.000 258.020 112.280 ;
      RECT 0.140 114.240 258.020 114.520 ;
      RECT 0.140 116.480 258.020 116.760 ;
      RECT 0.140 118.720 258.020 119.000 ;
      RECT 0.140 120.960 258.020 121.240 ;
      RECT 0.140 123.200 258.020 123.480 ;
      RECT 0.140 125.440 258.020 125.720 ;
      RECT 0.140 127.680 258.020 127.960 ;
      RECT 0.140 129.920 258.020 130.200 ;
      RECT 0.140 132.160 258.020 132.440 ;
      RECT 0.140 134.400 258.020 134.680 ;
      RECT 0.140 136.640 258.020 136.920 ;
      RECT 0.140 138.880 258.020 139.160 ;
      RECT 0.140 141.120 258.020 141.400 ;
      RECT 0.140 143.360 258.020 143.640 ;
      RECT 0.140 145.600 258.020 145.880 ;
      RECT 0.140 147.840 258.020 148.120 ;
      RECT 0.140 150.080 258.020 150.360 ;
      RECT 0.140 152.320 258.020 152.600 ;
      RECT 0.140 154.560 258.020 154.840 ;
      RECT 0.140 156.800 258.020 157.080 ;
      RECT 0.140 159.040 258.020 159.320 ;
      RECT 0.140 161.280 258.020 161.560 ;
      RECT 0.140 163.520 258.020 163.800 ;
      RECT 0.140 165.760 258.020 166.040 ;
      RECT 0.140 168.000 258.020 168.280 ;
      RECT 0.140 170.240 258.020 170.520 ;
      RECT 0.140 172.480 258.020 172.760 ;
      RECT 0.140 174.720 258.020 175.000 ;
      RECT 0.140 176.960 258.020 177.240 ;
      RECT 0.140 179.200 258.020 179.480 ;
      RECT 0.140 181.440 258.020 181.720 ;
      RECT 0.140 183.680 258.020 183.960 ;
      RECT 0.140 185.920 258.020 186.200 ;
      RECT 0.140 188.160 258.020 188.440 ;
      RECT 0.140 190.400 258.020 190.680 ;
      RECT 0.140 192.640 258.020 192.920 ;
      RECT 0.140 194.880 258.020 195.160 ;
      RECT 0.140 197.120 258.020 197.400 ;
      RECT 0.140 199.360 258.020 199.640 ;
      RECT 0.140 201.600 258.020 201.880 ;
      RECT 0.140 203.840 258.020 204.120 ;
      RECT 0.140 206.080 258.020 206.360 ;
      RECT 0.140 208.320 258.020 208.600 ;
      RECT 0.140 210.560 258.020 210.840 ;
      RECT 0.140 212.800 258.020 213.080 ;
      RECT 0.140 215.040 258.020 215.320 ;
      RECT 0.140 217.280 258.020 217.560 ;
      RECT 0.140 219.520 258.020 219.800 ;
      RECT 0.140 221.760 258.020 222.040 ;
      RECT 0.140 224.000 258.020 224.280 ;
      RECT 0.140 226.240 258.020 226.520 ;
      RECT 0.140 228.480 258.020 228.760 ;
      RECT 0.140 230.720 258.020 231.000 ;
      RECT 0.140 232.960 258.020 233.240 ;
      RECT 0.140 235.200 258.020 235.480 ;
      RECT 0.140 237.440 258.020 237.720 ;
      RECT 0.140 239.680 258.020 239.960 ;
      RECT 0.140 241.920 258.020 242.200 ;
      RECT 0.140 244.160 258.020 244.440 ;
      RECT 0.140 246.400 258.020 246.680 ;
      RECT 0.140 248.640 258.020 248.920 ;
      RECT 0.140 250.880 258.020 251.160 ;
      RECT 0.140 253.120 258.020 253.400 ;
      RECT 0.140 255.360 258.020 255.640 ;
      RECT 0.140 257.600 258.020 257.880 ;
      RECT 0.140 259.840 258.020 260.120 ;
      RECT 0.140 262.080 258.020 262.360 ;
      RECT 0.140 264.320 258.020 264.600 ;
      RECT 0.140 266.560 258.020 266.840 ;
      RECT 0.140 268.800 258.020 269.080 ;
      RECT 0.140 271.040 258.020 271.320 ;
      RECT 0.140 273.280 258.020 273.560 ;
      RECT 0.140 275.520 258.020 275.800 ;
      RECT 0.140 277.760 258.020 278.040 ;
      RECT 0.140 280.000 258.020 280.280 ;
      RECT 0.140 282.240 258.020 282.520 ;
      RECT 0.140 284.480 258.020 284.760 ;
      RECT 0.140 286.720 258.020 287.000 ;
      RECT 0.140 288.960 258.020 289.240 ;
      RECT 0.140 291.200 258.020 291.480 ;
      RECT 0.140 293.440 258.020 293.720 ;
      RECT 0.140 295.680 258.020 295.960 ;
      RECT 0.140 297.920 258.020 298.200 ;
      RECT 0.140 300.160 258.020 300.440 ;
      RECT 0.140 302.400 258.020 302.680 ;
      RECT 0.140 304.640 258.020 304.920 ;
      RECT 0.140 306.880 258.020 307.160 ;
      RECT 0.140 309.120 258.020 309.400 ;
      RECT 0.140 311.360 258.020 311.640 ;
      RECT 0.140 313.600 258.020 313.880 ;
      RECT 0.140 315.840 258.020 316.120 ;
      RECT 0.140 318.080 258.020 318.360 ;
      RECT 0.140 320.320 258.020 320.600 ;
      RECT 0.140 322.560 258.020 322.840 ;
    END
  END VSS
  PIN VDD
    DIRECTION INOUT ;
    USE POWER ;
    PORT
      LAYER metal3 ;
      RECT 0.140 1.120 258.020 1.400 ;
      RECT 0.140 3.360 258.020 3.640 ;
      RECT 0.140 5.600 258.020 5.880 ;
      RECT 0.140 7.840 258.020 8.120 ;
      RECT 0.140 10.080 258.020 10.360 ;
      RECT 0.140 12.320 258.020 12.600 ;
      RECT 0.140 14.560 258.020 14.840 ;
      RECT 0.140 16.800 258.020 17.080 ;
      RECT 0.140 19.040 258.020 19.320 ;
      RECT 0.140 21.280 258.020 21.560 ;
      RECT 0.140 23.520 258.020 23.800 ;
      RECT 0.140 25.760 258.020 26.040 ;
      RECT 0.140 28.000 258.020 28.280 ;
      RECT 0.140 30.240 258.020 30.520 ;
      RECT 0.140 32.480 258.020 32.760 ;
      RECT 0.140 34.720 258.020 35.000 ;
      RECT 0.140 36.960 258.020 37.240 ;
      RECT 0.140 39.200 258.020 39.480 ;
      RECT 0.140 41.440 258.020 41.720 ;
      RECT 0.140 43.680 258.020 43.960 ;
      RECT 0.140 45.920 258.020 46.200 ;
      RECT 0.140 48.160 258.020 48.440 ;
      RECT 0.140 50.400 258.020 50.680 ;
      RECT 0.140 52.640 258.020 52.920 ;
      RECT 0.140 54.880 258.020 55.160 ;
      RECT 0.140 57.120 258.020 57.400 ;
      RECT 0.140 59.360 258.020 59.640 ;
      RECT 0.140 61.600 258.020 61.880 ;
      RECT 0.140 63.840 258.020 64.120 ;
      RECT 0.140 66.080 258.020 66.360 ;
      RECT 0.140 68.320 258.020 68.600 ;
      RECT 0.140 70.560 258.020 70.840 ;
      RECT 0.140 72.800 258.020 73.080 ;
      RECT 0.140 75.040 258.020 75.320 ;
      RECT 0.140 77.280 258.020 77.560 ;
      RECT 0.140 79.520 258.020 79.800 ;
      RECT 0.140 81.760 258.020 82.040 ;
      RECT 0.140 84.000 258.020 84.280 ;
      RECT 0.140 86.240 258.020 86.520 ;
      RECT 0.140 88.480 258.020 88.760 ;
      RECT 0.140 90.720 258.020 91.000 ;
      RECT 0.140 92.960 258.020 93.240 ;
      RECT 0.140 95.200 258.020 95.480 ;
      RECT 0.140 97.440 258.020 97.720 ;
      RECT 0.140 99.680 258.020 99.960 ;
      RECT 0.140 101.920 258.020 102.200 ;
      RECT 0.140 104.160 258.020 104.440 ;
      RECT 0.140 106.400 258.020 106.680 ;
      RECT 0.140 108.640 258.020 108.920 ;
      RECT 0.140 110.880 258.020 111.160 ;
      RECT 0.140 113.120 258.020 113.400 ;
      RECT 0.140 115.360 258.020 115.640 ;
      RECT 0.140 117.600 258.020 117.880 ;
      RECT 0.140 119.840 258.020 120.120 ;
      RECT 0.140 122.080 258.020 122.360 ;
      RECT 0.140 124.320 258.020 124.600 ;
      RECT 0.140 126.560 258.020 126.840 ;
      RECT 0.140 128.800 258.020 129.080 ;
      RECT 0.140 131.040 258.020 131.320 ;
      RECT 0.140 133.280 258.020 133.560 ;
      RECT 0.140 135.520 258.020 135.800 ;
      RECT 0.140 137.760 258.020 138.040 ;
      RECT 0.140 140.000 258.020 140.280 ;
      RECT 0.140 142.240 258.020 142.520 ;
      RECT 0.140 144.480 258.020 144.760 ;
      RECT 0.140 146.720 258.020 147.000 ;
      RECT 0.140 148.960 258.020 149.240 ;
      RECT 0.140 151.200 258.020 151.480 ;
      RECT 0.140 153.440 258.020 153.720 ;
      RECT 0.140 155.680 258.020 155.960 ;
      RECT 0.140 157.920 258.020 158.200 ;
      RECT 0.140 160.160 258.020 160.440 ;
      RECT 0.140 162.400 258.020 162.680 ;
      RECT 0.140 164.640 258.020 164.920 ;
      RECT 0.140 166.880 258.020 167.160 ;
      RECT 0.140 169.120 258.020 169.400 ;
      RECT 0.140 171.360 258.020 171.640 ;
      RECT 0.140 173.600 258.020 173.880 ;
      RECT 0.140 175.840 258.020 176.120 ;
      RECT 0.140 178.080 258.020 178.360 ;
      RECT 0.140 180.320 258.020 180.600 ;
      RECT 0.140 182.560 258.020 182.840 ;
      RECT 0.140 184.800 258.020 185.080 ;
      RECT 0.140 187.040 258.020 187.320 ;
      RECT 0.140 189.280 258.020 189.560 ;
      RECT 0.140 191.520 258.020 191.800 ;
      RECT 0.140 193.760 258.020 194.040 ;
      RECT 0.140 196.000 258.020 196.280 ;
      RECT 0.140 198.240 258.020 198.520 ;
      RECT 0.140 200.480 258.020 200.760 ;
      RECT 0.140 202.720 258.020 203.000 ;
      RECT 0.140 204.960 258.020 205.240 ;
      RECT 0.140 207.200 258.020 207.480 ;
      RECT 0.140 209.440 258.020 209.720 ;
      RECT 0.140 211.680 258.020 211.960 ;
      RECT 0.140 213.920 258.020 214.200 ;
      RECT 0.140 216.160 258.020 216.440 ;
      RECT 0.140 218.400 258.020 218.680 ;
      RECT 0.140 220.640 258.020 220.920 ;
      RECT 0.140 222.880 258.020 223.160 ;
      RECT 0.140 225.120 258.020 225.400 ;
      RECT 0.140 227.360 258.020 227.640 ;
      RECT 0.140 229.600 258.020 229.880 ;
      RECT 0.140 231.840 258.020 232.120 ;
      RECT 0.140 234.080 258.020 234.360 ;
      RECT 0.140 236.320 258.020 236.600 ;
      RECT 0.140 238.560 258.020 238.840 ;
      RECT 0.140 240.800 258.020 241.080 ;
      RECT 0.140 243.040 258.020 243.320 ;
      RECT 0.140 245.280 258.020 245.560 ;
      RECT 0.140 247.520 258.020 247.800 ;
      RECT 0.140 249.760 258.020 250.040 ;
      RECT 0.140 252.000 258.020 252.280 ;
      RECT 0.140 254.240 258.020 254.520 ;
      RECT 0.140 256.480 258.020 256.760 ;
      RECT 0.140 258.720 258.020 259.000 ;
      RECT 0.140 260.960 258.020 261.240 ;
      RECT 0.140 263.200 258.020 263.480 ;
      RECT 0.140 265.440 258.020 265.720 ;
      RECT 0.140 267.680 258.020 267.960 ;
      RECT 0.140 269.920 258.020 270.200 ;
      RECT 0.140 272.160 258.020 272.440 ;
      RECT 0.140 274.400 258.020 274.680 ;
      RECT 0.140 276.640 258.020 276.920 ;
      RECT 0.140 278.880 258.020 279.160 ;
      RECT 0.140 281.120 258.020 281.400 ;
      RECT 0.140 283.360 258.020 283.640 ;
      RECT 0.140 285.600 258.020 285.880 ;
      RECT 0.140 287.840 258.020 288.120 ;
      RECT 0.140 290.080 258.020 290.360 ;
      RECT 0.140 292.320 258.020 292.600 ;
      RECT 0.140 294.560 258.020 294.840 ;
      RECT 0.140 296.800 258.020 297.080 ;
      RECT 0.140 299.040 258.020 299.320 ;
      RECT 0.140 301.280 258.020 301.560 ;
      RECT 0.140 303.520 258.020 303.800 ;
      RECT 0.140 305.760 258.020 306.040 ;
      RECT 0.140 308.000 258.020 308.280 ;
      RECT 0.140 310.240 258.020 310.520 ;
      RECT 0.140 312.480 258.020 312.760 ;
      RECT 0.140 314.720 258.020 315.000 ;
      RECT 0.140 316.960 258.020 317.240 ;
      RECT 0.140 319.200 258.020 319.480 ;
      RECT 0.140 321.440 258.020 321.720 ;
    END
  END VDD
  OBS
    LAYER metal1 ;
    RECT 0 0 258.160 323.400 ;
    LAYER metal2 ;
    RECT 0 0 258.160 323.400 ;
  END
END fakeram_128x512
END LIBRARY
